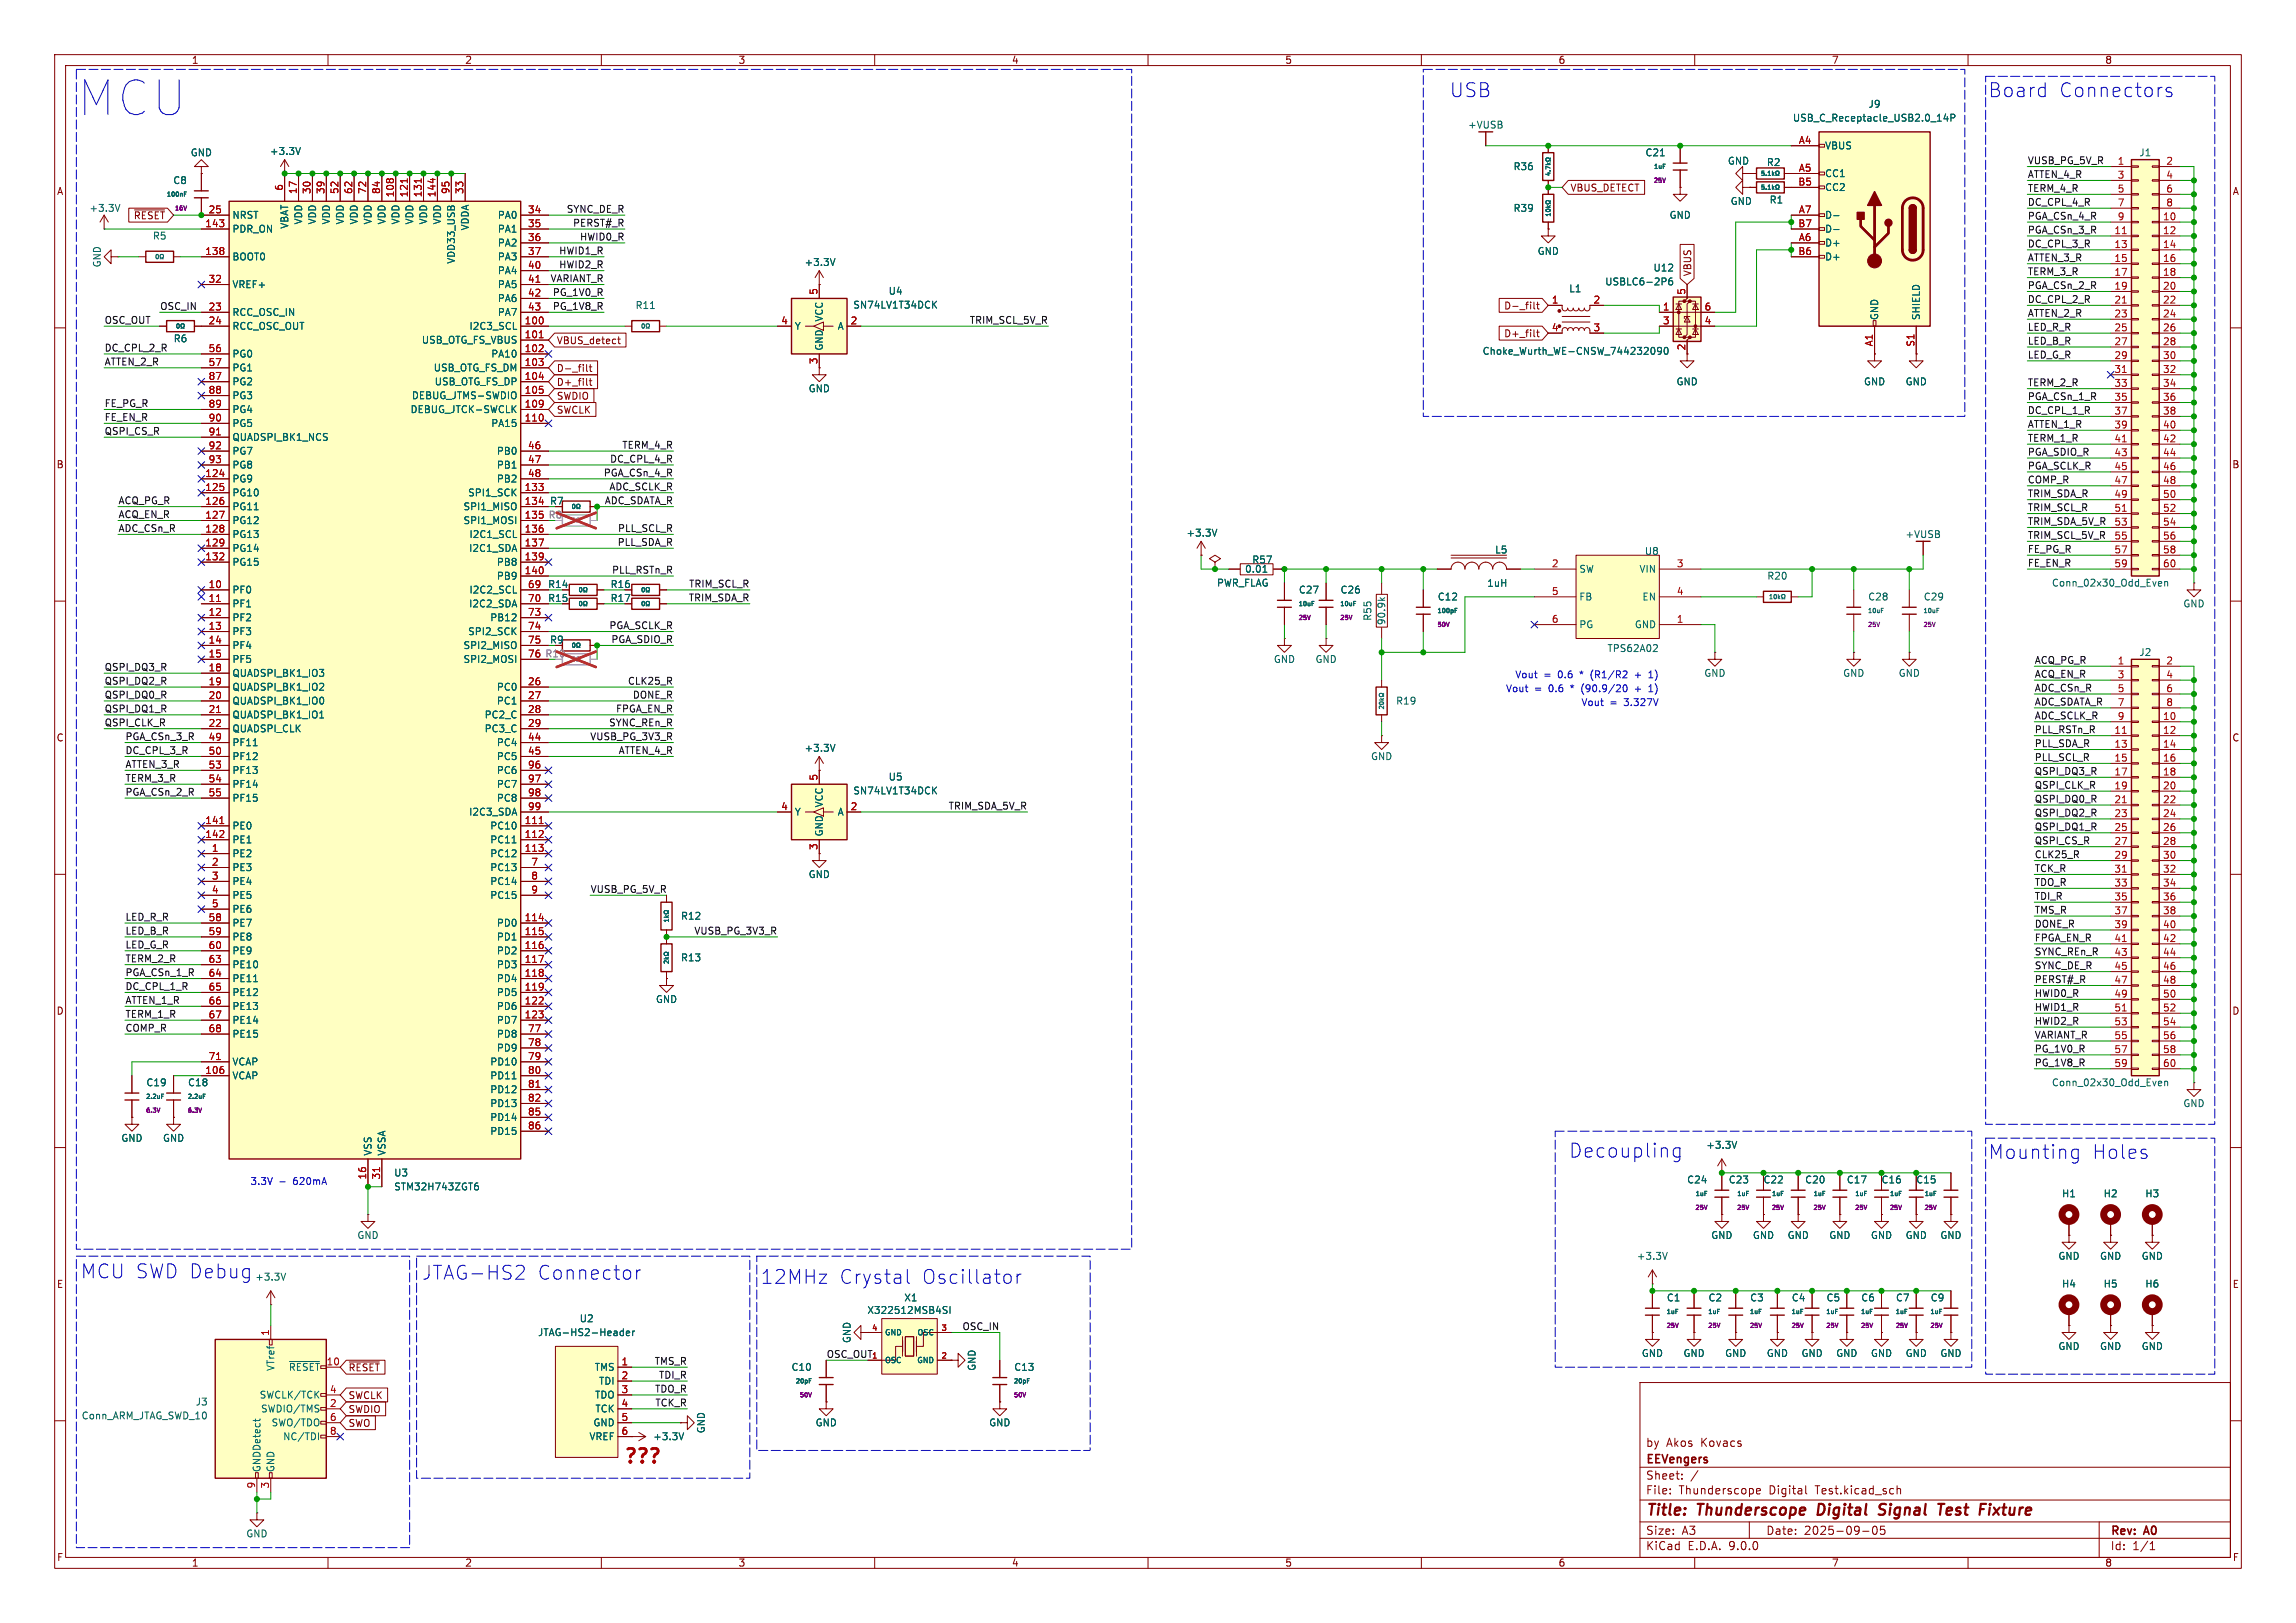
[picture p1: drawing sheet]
<svg xmlns="http://www.w3.org/2000/svg" width="420mm" height="297mm" viewBox="0 0 420 297" stroke-linecap="round" stroke-linejoin="round" font-family="sans-serif">
<defs><g id="words">
<text font-size="8.8" fill="#0000c2" x="14.4" y="21.4">MCU</text>
<g font-size="3.5" fill="#0000c2">
<text x="265.2" y="18">USB</text>
<text x="363.7" y="18">Board</text>
<text x="376.6" y="18">Connectors</text>
<text x="287" y="212.1">Decoupling</text>
<text x="363.7" y="212.3">Mounting</text>
<text x="382.7" y="212.3">Holes</text>
<text x="14.8" y="234.2">MCU SWD Debug</text>
<text x="77.2" y="234.4">JTAG-HS2</text>
<text x="98.3" y="234.4">Connector</text>
<text x="139.1" y="235.2">12MHz</text>
<text x="153.5" y="235.2">Crystal</text>
<text x="168.6" y="235.2">Oscillator</text>
</g>
<text font-size="3.5" fill="#c20000" x="113.8" y="268.5">???</text>
<g font-size="2.8" fill="#840000">
<text x="301" y="277.9">Title:</text>
<text x="310.6" y="277.9">Thunderscope</text>
<text x="333.4" y="277.9">Digital</text>
<text x="345.4" y="277.9">Signal</text>
<text x="357" y="277.9">Test</text>
<text x="365.4" y="277.9">Fixture</text>
</g>
<g font-size="2.1" fill="#840000">
<text x="301" y="268.2">EEVengers</text>
<text x="301" y="265">by</text>
<text x="304.8" y="265">Akos</text>
<text x="311.2" y="265">Kovacs</text>
<text x="301" y="273.7">File:</text>
<text x="301" y="271">Sheet:</text>
<text x="307.1" y="273.7">Thunderscope</text>
<text x="323.7" y="273.7">Digital</text>
<text x="332.2" y="273.7">Test.kicad_sch</text>
<text x="301" y="281.1">Size:</text>
<text x="307.6" y="281.1">A3</text>
<text x="323" y="281.1">Date:</text>
<text x="330" y="281.1">2025-09-05</text>
<text x="386" y="281.3">Rev:</text>
<text x="392.4" y="281.3">A0</text>
<text x="301" y="283.9">KiCad</text>
<text x="308.7" y="283.9">E.D.A.</text>
<text x="316.3" y="283.9">9.0.0</text>
<text x="386" y="283.9">Id:</text>
<text x="390.1" y="283.9">1/1</text>
</g>
<g font-size="1.8" fill="#840000">
<text x="35" y="11.9">1</text>
<text x="85" y="11.9">2</text>
<text x="135" y="11.9">3</text>
<text x="185" y="11.9">4</text>
<text x="235" y="11.9">5</text>
<text x="285" y="11.9">6</text>
<text x="335" y="11.9">7</text>
<text x="385" y="11.9">8</text>
<text x="10.3" y="35.9">A</text>
<text x="287.2" y="35.2">VBUS_DETECT</text>
<text x="408.3" y="35.9">A</text>
<text x="24.4" y="40.3">~{RESET}</text>
<text x="309.6" y="50.6" transform="rotate(-90 309.6 50.6)">VBUS</text>
<text x="275" y="56.8">D-_filt</text>
<text x="101.8" y="63.2">VBUS_detect</text>
<text x="275" y="61.9">D+_filt</text>
<text x="308.4" y="64.2" transform="rotate(-90 308.4 64.2)">2</text>
<text x="101.8" y="70.8">D+_filt</text>
<text x="101.8" y="68.3">D-_filt</text>
<text x="101.8" y="73.3">SWDIO</text>
<text x="101.8" y="75.9">SWCLK</text>
<text x="10.3" y="85.9">B</text>
<text x="408.2" y="85.9">B</text>
<text x="100.5" y="92.6">R7</text>
<text x="100.5" y="118">R9</text>
<text x="10.3" y="135.9">C</text>
<text x="408.2" y="135.9">C</text>
<text x="10.3" y="185.9">D</text>
<text x="408.2" y="185.9">D</text>
<text x="10.3" y="235.9">E</text>
<text x="408.3" y="235.9">E</text>
<text x="63.7" y="251.1">~{RESET}</text>
<text x="63.7" y="256.2">SWCLK</text>
<text x="63.7" y="261.3">SWO</text>
<text x="63.7" y="258.8">SWDIO</text>
<text x="10.3" y="285.9">F</text>
<text x="35" y="286.9">1</text>
<text x="85" y="286.9">2</text>
<text x="135" y="286.9">3</text>
<text x="185" y="286.9">4</text>
<text x="235" y="286.9">5</text>
<text x="285" y="286.9">6</text>
<text x="335" y="286.9">7</text>
<text x="385" y="286.9">8</text>
<text x="408.3" y="285.9">F</text>
</g>
<g font-size="1.8" fill="#006464">
<text x="268.4" y="23.7">+VUSB</text>
<text x="327.9" y="22.5">USB_C_Receptacle_USB2.0_14P</text>
<text x="341.7" y="19.9">J9</text>
<text x="34.8" y="28.8">GND</text>
<text x="49.3" y="28.5">+3.3V</text>
<text x="300.9" y="28.8">C21</text>
<text x="333.8" y="27.5">VBUS</text>
<text x="391.2" y="28.8">J1</text>
<text x="31.6" y="33.9">C8</text>
<text x="276.8" y="31.3">R36</text>
<text x="316" y="30.3">GND</text>
<text x="323.1" y="30.6">R2</text>
<text x="333.8" y="32.6">CC1</text>
<text x="333.8" y="35.2">CC2</text>
<text x="16.3" y="39">+3.3V</text>
<text x="42.4" y="40.2">NRST</text>
<text x="52.9" y="42" transform="rotate(-90 52.9 42)">VBAT</text>
<text x="55.5" y="41.2" transform="rotate(-90 55.5 41.2)">VDD</text>
<text x="58" y="41.2" transform="rotate(-90 58 41.2)">VDD</text>
<text x="60.6" y="41.2" transform="rotate(-90 60.6 41.2)">VDD</text>
<text x="63.1" y="41.2" transform="rotate(-90 63.1 41.2)">VDD</text>
<text x="65.6" y="41.2" transform="rotate(-90 65.6 41.2)">VDD</text>
<text x="68.2" y="41.2" transform="rotate(-90 68.2 41.2)">VDD</text>
<text x="70.7" y="41.2" transform="rotate(-90 70.7 41.2)">VDD</text>
<text x="73.3" y="41.2" transform="rotate(-90 73.3 41.2)">VDD</text>
<text x="75.8" y="41.2" transform="rotate(-90 75.8 41.2)">VDD</text>
<text x="78.3" y="41.2" transform="rotate(-90 78.3 41.2)">VDD</text>
<text x="80.9" y="41.2" transform="rotate(-90 80.9 41.2)">VDD</text>
<text x="91" y="40.2">PA0</text>
<text x="276.8" y="39">R39</text>
<text x="305.3" y="40.2">GND</text>
<text x="316.5" y="37.7">GND</text>
<text x="323.6" y="37.4">R1</text>
<text x="333.8" y="40.2">D-</text>
<text x="27.9" y="44">R5</text>
<text x="42.4" y="42.8">PDR_ON</text>
<text x="42.4" y="47.9">BOOT0</text>
<text x="86" y="42.3" transform="rotate(-90 86 42.3)">VDDA</text>
<text x="91" y="42.8">PA1</text>
<text x="91" y="45.3">PA2</text>
<text x="91" y="47.9">PA3</text>
<text x="281.2" y="46.8">GND</text>
<text x="333.8" y="42.8">D-</text>
<text x="333.8" y="45.3">D+</text>
<text x="333.8" y="47.9">D+</text>
<text x="18.6" y="49" transform="rotate(-90 18.6 49)">GND</text>
<text x="42.4" y="52.9">VREF+</text>
<text x="83.4" y="48.4" transform="rotate(-90 83.4 48.4)">VDD33_USB</text>
<text x="91" y="50.4">PA4</text>
<text x="91" y="52.9">PA5</text>
<text x="147.1" y="48.9">+3.3V</text>
<text x="286.9" y="53.7">L1</text>
<text x="293.5" y="52.4">USBLC6-2P6</text>
<text x="302.4" y="49.9">U12</text>
<text x="42.4" y="58">RCC_OSC_IN</text>
<text x="91" y="55.5">PA6</text>
<text x="91" y="58">PA7</text>
<text x="116.2" y="56.7">R11</text>
<text x="150.7" y="58.9" transform="rotate(-90 150.7 58.9)">VCC</text>
<text x="156" y="56.7">SN74LV1T34DCK</text>
<text x="162.5" y="54.1">U4</text>
<text x="343.8" y="58.7" transform="rotate(-90 343.8 58.7)">GND</text>
<text x="351.4" y="58.7" transform="rotate(-90 351.4 58.7)">SHIELD</text>
<text x="31.7" y="62.8">R6</text>
<text x="42.4" y="60.6">RCC_OSC_OUT</text>
<text x="42.4" y="65.6">PG0</text>
<text x="77.1" y="63.1">USB_OTG_FS_VBUS</text>
<text x="85.8" y="60.6">I2C3_SCL</text>
<text x="89.8" y="65.6">PA10</text>
<text x="145.3" y="60.6">Y</text>
<text x="150.7" y="64.3" transform="rotate(-90 150.7 64.3)">GND</text>
<text x="153.1" y="60.6">A</text>
<text x="271.1" y="65.1">Choke_Wurth_WE-CNSW_744232090</text>
<text x="42.4" y="68.2">PG1</text>
<text x="42.4" y="70.7">PG2</text>
<text x="79.2" y="68.2">USB_OTG_FS_DM</text>
<text x="79.4" y="70.7">USB_OTG_FS_DP</text>
<text x="147.8" y="72">GND</text>
<text x="306.6" y="70.7">GND</text>
<text x="340.9" y="70.7">GND</text>
<text x="348.5" y="70.7">GND</text>
<text x="42.4" y="73.3">PG3</text>
<text x="42.4" y="75.8">PG4</text>
<text x="75" y="75.8">DEBUG_JTCK-SWCLK</text>
<text x="75.2" y="73.3">DEBUG_JTMS-SWDIO</text>
<text x="42.4" y="78.3">PG5</text>
<text x="42.4" y="80.9">QUADSPI_BK1_NCS</text>
<text x="42.4" y="83.4">PG7</text>
<text x="89.8" y="78.3">PA15</text>
<text x="90.8" y="83.4">PB0</text>
<text x="42.4" y="86">PG8</text>
<text x="42.4" y="88.5">PG9</text>
<text x="90.8" y="86">PB1</text>
<text x="90.8" y="88.5">PB2</text>
<text x="42.4" y="91">PG10</text>
<text x="42.4" y="93.6">PG11</text>
<text x="84.7" y="93.6">SPI1_MISO</text>
<text x="85.5" y="91">SPI1_SCK</text>
<text x="42.4" y="96.1">PG12</text>
<text x="42.4" y="98.7">PG13</text>
<text x="42.4" y="101.2">PG14</text>
<text x="84.7" y="96.1">SPI1_MOSI</text>
<text x="85.7" y="101.2">I2C1_SDA</text>
<text x="85.8" y="98.7">I2C1_SCL</text>
<text x="216.9" y="98.4">+3.3V</text>
<text x="273.4" y="101.5">L5</text>
<text x="300.8" y="101.7">U8</text>
<text x="348.5" y="98.7">+VUSB</text>
<text x="42.4" y="103.7">PG15</text>
<text x="90.8" y="103.7">PB8</text>
<text x="90.8" y="106.3">PB9</text>
<text x="100.2" y="107.8">R14</text>
<text x="111.6" y="107.8">R16</text>
<text x="222.5" y="107.5">PWR_FLAG</text>
<text x="227.7" y="105">0.01</text>
<text x="229" y="103.3">R57</text>
<text x="271.9" y="107.6">1uH</text>
<text x="288.8" y="105">SW</text>
<text x="299.8" y="105">VIN</text>
<text x="323.2" y="106.3">R20</text>
<text x="375.2" y="107.5">Conn_02x30_Odd_Even</text>
<text x="42.4" y="108.8">PF0</text>
<text x="42.4" y="111.4">PF1</text>
<text x="42.4" y="113.9">PF2</text>
<text x="85.7" y="111.4">I2C2_SDA</text>
<text x="85.8" y="108.8">I2C2_SCL</text>
<text x="89.6" y="113.9">PB12</text>
<text x="100.2" y="110.3">R15</text>
<text x="111.6" y="110.3">R17</text>
<text x="237.5" y="108.8">C27</text>
<text x="245.1" y="108.8">C26</text>
<text x="251.1" y="113.7" transform="rotate(-90 251.1 113.7)">R55</text>
<text x="262.9" y="110.1">C12</text>
<text x="288.8" y="110.1">FB</text>
<text x="300.3" y="110.1">EN</text>
<text x="341.6" y="110.1">C28</text>
<text x="351.8" y="110.1">C29</text>
<text x="399.3" y="111.4">GND</text>
<text x="42.4" y="116.4">PF3</text>
<text x="42.4" y="119">PF4</text>
<text x="84.7" y="119">SPI2_MISO</text>
<text x="85.5" y="116.4">SPI2_SCK</text>
<text x="253.6" y="114.5" transform="rotate(-90 253.6 114.5)">90.9k</text>
<text x="288.8" y="115.2">PG</text>
<text x="293.9" y="119.5">TPS62A02</text>
<text x="298.9" y="115.2">GND</text>
<text x="42.4" y="121.5">PF5</text>
<text x="42.4" y="124.1">QUADSPI_BK1_IO3</text>
<text x="84.7" y="121.5">SPI2_MOSI</text>
<text x="232.9" y="121.5">GND</text>
<text x="240.5" y="121.5">GND</text>
<text x="311.7" y="124.1">GND</text>
<text x="337.1" y="124.1">GND</text>
<text x="347.2" y="124.1">GND</text>
<text x="391.2" y="120.2">J2</text>
<text x="42.4" y="126.6">QUADSPI_BK1_IO2</text>
<text x="42.4" y="129.1">QUADSPI_BK1_IO0</text>
<text x="42.4" y="131.7">QUADSPI_BK1_IO1</text>
<text x="88.6" y="131.7">PC2_C</text>
<text x="90.8" y="126.6">PC0</text>
<text x="90.8" y="129.1">PC1</text>
<text x="255.3" y="129.1">R19</text>
<text x="42.4" y="134.2">QUADSPI_CLK</text>
<text x="42.4" y="136.8">PF11</text>
<text x="88.6" y="134.2">PC3_C</text>
<text x="90.8" y="136.8">PC4</text>
<text x="147.1" y="137.8">+3.3V</text>
<text x="42.4" y="139.3">PF12</text>
<text x="42.4" y="141.8">PF13</text>
<text x="90.8" y="139.3">PC5</text>
<text x="90.8" y="141.8">PC6</text>
<text x="162.5" y="143">U5</text>
<text x="250.7" y="139.3">GND</text>
<text x="42.4" y="144.4">PF14</text>
<text x="42.4" y="146.9">PF15</text>
<text x="85.7" y="149.5">I2C3_SDA</text>
<text x="90.8" y="144.4">PC7</text>
<text x="90.8" y="146.9">PC8</text>
<text x="145.3" y="149.5">Y</text>
<text x="150.7" y="147.8" transform="rotate(-90 150.7 147.8)">VCC</text>
<text x="153.1" y="149.5">A</text>
<text x="156" y="145.6">SN74LV1T34DCK</text>
<text x="42.4" y="152">PE0</text>
<text x="42.4" y="154.5">PE1</text>
<text x="89.6" y="152">PC10</text>
<text x="89.6" y="154.5">PC11</text>
<text x="150.7" y="153.2" transform="rotate(-90 150.7 153.2)">GND</text>
<text x="42.4" y="157.1">PE2</text>
<text x="42.4" y="159.6">PE3</text>
<text x="89.6" y="157.1">PC12</text>
<text x="89.6" y="159.6">PC13</text>
<text x="147.8" y="160.9">GND</text>
<text x="42.4" y="162.2">PE4</text>
<text x="42.4" y="164.7">PE5</text>
<text x="42.4" y="167.2">PE6</text>
<text x="89.6" y="162.2">PC14</text>
<text x="89.6" y="164.7">PC15</text>
<text x="42.4" y="169.8">PE7</text>
<text x="42.4" y="172.3">PE8</text>
<text x="90.8" y="169.8">PD0</text>
<text x="90.8" y="172.3">PD1</text>
<text x="124.5" y="168.5">R12</text>
<text x="42.4" y="174.9">PE9</text>
<text x="42.4" y="177.4">PE10</text>
<text x="42.4" y="179.9">PE11</text>
<text x="90.8" y="174.9">PD2</text>
<text x="90.8" y="177.4">PD3</text>
<text x="90.8" y="179.9">PD4</text>
<text x="124.5" y="176.1">R13</text>
<text x="42.4" y="182.5">PE12</text>
<text x="42.4" y="185">PE13</text>
<text x="90.8" y="182.5">PD5</text>
<text x="90.8" y="185">PD6</text>
<text x="119.9" y="183.7">GND</text>
<text x="42.4" y="187.6">PE14</text>
<text x="42.4" y="190.1">PE15</text>
<text x="90.8" y="187.6">PD7</text>
<text x="90.8" y="190.1">PD8</text>
<text x="42.4" y="195.2">VCAP</text>
<text x="42.4" y="197.7">VCAP</text>
<text x="89.6" y="195.2">PD10</text>
<text x="89.6" y="197.7">PD11</text>
<text x="90.8" y="192.6">PD9</text>
<text x="26.7" y="199">C19</text>
<text x="34.3" y="199">C18</text>
<text x="89.6" y="200.3">PD12</text>
<text x="89.6" y="202.8">PD13</text>
<text x="375.2" y="199">Conn_02x30_Odd_Even</text>
<text x="399.3" y="202.8">GND</text>
<text x="22.1" y="209.1">GND</text>
<text x="29.7" y="209.1">GND</text>
<text x="89.6" y="205.3">PD14</text>
<text x="89.6" y="207.9">PD15</text>
<text x="68.2" y="211.6" transform="rotate(-90 68.2 211.6)">VSS</text>
<text x="70.7" y="211.6" transform="rotate(-90 70.7 211.6)">VSSA</text>
<text x="72" y="215.5">U3</text>
<text x="312" y="210.4">+3.3V</text>
<text x="72" y="218">STM32H743ZGT6</text>
<text x="308.5" y="216.8">C24</text>
<text x="316.1" y="216.8">C23</text>
<text x="322.5" y="216.8">C22</text>
<text x="330.1" y="216.8">C20</text>
<text x="337.7" y="216.8">C17</text>
<text x="344.1" y="216.8">C16</text>
<text x="350.4" y="216.8">C15</text>
<text x="377.1" y="219.3">H1</text>
<text x="384.7" y="219.3">H2</text>
<text x="392.3" y="219.3">H3</text>
<text x="65.3" y="226.9">GND</text>
<text x="312.9" y="226.9">GND</text>
<text x="320.5" y="226.9">GND</text>
<text x="326.9" y="226.9">GND</text>
<text x="334.5" y="226.9">GND</text>
<text x="342.1" y="226.9">GND</text>
<text x="348.5" y="226.9">GND</text>
<text x="354.8" y="226.9">GND</text>
<text x="299.3" y="230.7">+3.3V</text>
<text x="376.4" y="230.7">GND</text>
<text x="384" y="230.7">GND</text>
<text x="391.7" y="230.7">GND</text>
<text x="46.6" y="234.5">+3.3V</text>
<text x="165.3" y="238.4">X1</text>
<text x="304.8" y="238.4">C1</text>
<text x="312.4" y="238.4">C2</text>
<text x="320" y="238.4">C3</text>
<text x="327.7" y="238.4">C4</text>
<text x="334" y="238.4">C5</text>
<text x="340.4" y="238.4">C6</text>
<text x="346.7" y="238.4">C7</text>
<text x="353.1" y="238.4">C9</text>
<text x="377.1" y="235.8">H4</text>
<text x="384.7" y="235.8">H5</text>
<text x="392.3" y="235.8">H6</text>
<text x="98.3" y="244.7">JTAG-HS2-Header</text>
<text x="105.9" y="242.2">U2</text>
<text x="155.8" y="245.9" transform="rotate(-90 155.8 245.9)">GND</text>
<text x="158.6" y="240.6">X322512MSB4SI</text>
<text x="50.4" y="251" transform="rotate(-90 50.4 251)">VTref</text>
<text x="52.7" y="251.1">~{RESET}</text>
<text x="108.7" y="251.1">TMS</text>
<text x="144.7" y="251.1">C10</text>
<text x="178.7" y="251" transform="rotate(-90 178.7 251)">GND</text>
<text x="185.4" y="251.1">C13</text>
<text x="300.2" y="248.5">GND</text>
<text x="307.8" y="248.5">GND</text>
<text x="315.5" y="248.5">GND</text>
<text x="323.1" y="248.5">GND</text>
<text x="329.4" y="248.5">GND</text>
<text x="335.8" y="248.5">GND</text>
<text x="342.1" y="248.5">GND</text>
<text x="348.5" y="248.5">GND</text>
<text x="354.8" y="248.5">GND</text>
<text x="376.4" y="247.2">GND</text>
<text x="384" y="247.2">GND</text>
<text x="391.7" y="247.2">GND</text>
<text x="35.7" y="257.4">J3</text>
<text x="47.4" y="256.1">SWCLK/TCK</text>
<text x="108.8" y="256.1">TDO</text>
<text x="109.5" y="253.6">TDI</text>
<text x="14.8" y="259.9">Conn_ARM_JTAG_SWD_10</text>
<text x="47.6" y="258.7">SWDIO/TMS</text>
<text x="49.6" y="261.2">SWO/TDO</text>
<text x="51.7" y="263.8">NC/TDI</text>
<text x="107.7" y="263.8">VREF</text>
<text x="108.4" y="261.2">GND</text>
<text x="108.8" y="258.7">TCK</text>
<text x="119.4" y="263.8">+3.3V</text>
<text x="129.1" y="262.4" transform="rotate(-90 129.1 262.4)">GND</text>
<text x="149.1" y="261.2">GND</text>
<text x="180.8" y="261.2">GND</text>
<text x="47.9" y="269.5" transform="rotate(-90 47.9 269.5)">GNDDetect</text>
<text x="50.4" y="269.5" transform="rotate(-90 50.4 269.5)">GND</text>
<text x="45" y="281.5">GND</text>
</g>
<g font-size="1.8" fill="#a90000">
<text x="328.9" y="26.4">A4</text>
<text x="51.8" y="35" transform="rotate(-90 51.8 35)">6</text>
<text x="54.4" y="35.6" transform="rotate(-90 54.4 35.6)">17</text>
<text x="56.9" y="35.6" transform="rotate(-90 56.9 35.6)">30</text>
<text x="59.4" y="35.6" transform="rotate(-90 59.4 35.6)">39</text>
<text x="62" y="35.6" transform="rotate(-90 62 35.6)">52</text>
<text x="64.5" y="35.6" transform="rotate(-90 64.5 35.6)">62</text>
<text x="67.1" y="35.6" transform="rotate(-90 67.1 35.6)">72</text>
<text x="69.6" y="35.6" transform="rotate(-90 69.6 35.6)">84</text>
<text x="82.3" y="35.6" transform="rotate(-90 82.3 35.6)">95</text>
<text x="84.8" y="35.6" transform="rotate(-90 84.8 35.6)">33</text>
<text x="328.9" y="34">B5</text>
<text x="328.9" y="31.5">A5</text>
<text x="387.3" y="30.2">1</text>
<text x="387.3" y="32.8">3</text>
<text x="387.3" y="35.3">5</text>
<text x="396.2" y="30.2">2</text>
<text x="396.2" y="32.8">4</text>
<text x="396.2" y="35.3">6</text>
<text x="37.5" y="41.7">143</text>
<text x="38.1" y="39.1">25</text>
<text x="72.1" y="36.2" transform="rotate(-90 72.1 36.2)">108</text>
<text x="74.7" y="36.2" transform="rotate(-90 74.7 36.2)">121</text>
<text x="77.2" y="36.2" transform="rotate(-90 77.2 36.2)">131</text>
<text x="79.8" y="36.2" transform="rotate(-90 79.8 36.2)">144</text>
<text x="96.5" y="39.1">34</text>
<text x="96.5" y="41.7">35</text>
<text x="328.9" y="41.7">B7</text>
<text x="328.9" y="39.1">A7</text>
<text x="387.3" y="37.8">7</text>
<text x="387.3" y="40.4">9</text>
<text x="395.6" y="40.4">10</text>
<text x="396.2" y="37.8">8</text>
<text x="37.5" y="46.7">138</text>
<text x="96.5" y="44.2">36</text>
<text x="96.5" y="46.7">37</text>
<text x="328.9" y="46.7">B6</text>
<text x="328.9" y="44.2">A6</text>
<text x="386.7" y="42.9">11</text>
<text x="386.7" y="45.5">13</text>
<text x="395.6" y="42.9">12</text>
<text x="395.6" y="45.5">14</text>
<text x="38.1" y="51.8">32</text>
<text x="96.5" y="49.3">40</text>
<text x="96.5" y="51.8">41</text>
<text x="386.7" y="48">15</text>
<text x="386.7" y="50.5">17</text>
<text x="386.7" y="53.1">19</text>
<text x="395.6" y="48">16</text>
<text x="395.6" y="50.5">18</text>
<text x="395.6" y="53.1">20</text>
<text x="38.1" y="56.9">23</text>
<text x="38.1" y="59.4">24</text>
<text x="95.9" y="59.4">100</text>
<text x="96.5" y="54.4">42</text>
<text x="96.5" y="56.9">43</text>
<text x="142.8" y="59.4">4</text>
<text x="149.6" y="54" transform="rotate(-90 149.6 54)">5</text>
<text x="155.5" y="59.4">2</text>
<text x="283.8" y="55.6">1</text>
<text x="291.4" y="55.6">2</text>
<text x="304.1" y="56.9">1</text>
<text x="304.1" y="59.4">3</text>
<text x="308.4" y="54" transform="rotate(-90 308.4 54)">5</text>
<text x="311.7" y="56.9">6</text>
<text x="311.7" y="59.4">4</text>
<text x="386.7" y="55.6">21</text>
<text x="386.7" y="58.2">23</text>
<text x="395.6" y="55.6">22</text>
<text x="395.6" y="58.2">24</text>
<text x="38.1" y="64.5">56</text>
<text x="95.9" y="62">101</text>
<text x="95.9" y="64.5">102</text>
<text x="283.8" y="60.7">4</text>
<text x="291.4" y="60.7">3</text>
<text x="342.6" y="63.5" transform="rotate(-90 342.6 63.5)">A1</text>
<text x="350.3" y="63.5" transform="rotate(-90 350.3 63.5)">S1</text>
<text x="386.7" y="60.7">25</text>
<text x="386.7" y="63.2">27</text>
<text x="386.7" y="65.8">29</text>
<text x="395.6" y="60.7">26</text>
<text x="395.6" y="63.2">28</text>
<text x="395.6" y="65.8">30</text>
<text x="38.1" y="67.1">57</text>
<text x="38.1" y="69.6">87</text>
<text x="95.9" y="67.1">103</text>
<text x="95.9" y="69.6">104</text>
<text x="149.6" y="66.7" transform="rotate(-90 149.6 66.7)">3</text>
<text x="386.7" y="68.3">31</text>
<text x="386.7" y="70.9">33</text>
<text x="395.6" y="68.3">32</text>
<text x="395.6" y="70.9">34</text>
<text x="38.1" y="72.1">88</text>
<text x="38.1" y="74.7">89</text>
<text x="38.1" y="77.2">90</text>
<text x="95.9" y="72.1">105</text>
<text x="95.9" y="74.7">109</text>
<text x="95.9" y="77.2">110</text>
<text x="386.7" y="73.4">35</text>
<text x="386.7" y="75.9">37</text>
<text x="395.6" y="73.4">36</text>
<text x="395.6" y="75.9">38</text>
<text x="38.1" y="79.8">91</text>
<text x="38.1" y="82.3">92</text>
<text x="96.5" y="82.3">46</text>
<text x="386.7" y="78.5">39</text>
<text x="386.7" y="81">41</text>
<text x="386.7" y="83.6">43</text>
<text x="395.6" y="78.5">40</text>
<text x="395.6" y="81">42</text>
<text x="395.6" y="83.6">44</text>
<text x="37.5" y="87.4">124</text>
<text x="37.5" y="89.9">125</text>
<text x="38.1" y="84.8">93</text>
<text x="95.9" y="89.9">133</text>
<text x="96.5" y="84.8">47</text>
<text x="96.5" y="87.4">48</text>
<text x="386.7" y="86.1">45</text>
<text x="386.7" y="88.6">47</text>
<text x="395.6" y="86.1">46</text>
<text x="395.6" y="88.6">48</text>
<text x="37.5" y="92.5">126</text>
<text x="37.5" y="95">127</text>
<text x="95.9" y="92.5">134</text>
<text x="95.9" y="95">135</text>
<text x="386.7" y="91.2">49</text>
<text x="386.7" y="93.7">51</text>
<text x="395.6" y="91.2">50</text>
<text x="395.6" y="93.7">52</text>
<text x="37.5" y="97.5">128</text>
<text x="37.5" y="100.1">129</text>
<text x="95.9" y="97.5">136</text>
<text x="95.9" y="100.1">137</text>
<text x="386.7" y="96.3">53</text>
<text x="386.7" y="98.8">55</text>
<text x="386.7" y="101.3">57</text>
<text x="395.6" y="96.3">54</text>
<text x="395.6" y="98.8">56</text>
<text x="395.6" y="101.3">58</text>
<text x="37.5" y="102.6">132</text>
<text x="38.1" y="107.7">10</text>
<text x="95.9" y="102.6">139</text>
<text x="95.9" y="105.2">140</text>
<text x="96.5" y="107.7">69</text>
<text x="283.8" y="103.9">2</text>
<text x="306.6" y="103.9">3</text>
<text x="386.7" y="103.9">59</text>
<text x="395.6" y="103.9">60</text>
<text x="38.1" y="110.2">11</text>
<text x="38.1" y="112.8">12</text>
<text x="96.5" y="110.2">70</text>
<text x="96.5" y="112.8">73</text>
<text x="283.8" y="109">5</text>
<text x="306.6" y="109">4</text>
<text x="38.1" y="115.3">13</text>
<text x="38.1" y="117.9">14</text>
<text x="96.5" y="115.3">74</text>
<text x="96.5" y="117.9">75</text>
<text x="283.8" y="114">6</text>
<text x="306.6" y="114">1</text>
<text x="38.1" y="120.4">15</text>
<text x="38.1" y="122.9">18</text>
<text x="38.1" y="125.5">19</text>
<text x="96.5" y="125.5">26</text>
<text x="387.3" y="121.7">1</text>
<text x="387.3" y="124.2">3</text>
<text x="396.2" y="121.7">2</text>
<text x="396.2" y="124.2">4</text>
<text x="38.1" y="128">20</text>
<text x="38.1" y="130.6">21</text>
<text x="96.5" y="128">27</text>
<text x="96.5" y="130.6">28</text>
<text x="387.3" y="126.7">5</text>
<text x="387.3" y="129.3">7</text>
<text x="387.3" y="131.8">9</text>
<text x="395.6" y="131.8">10</text>
<text x="396.2" y="126.7">6</text>
<text x="396.2" y="129.3">8</text>
<text x="38.1" y="133.1">22</text>
<text x="38.1" y="135.6">49</text>
<text x="96.5" y="133.1">29</text>
<text x="96.5" y="135.6">44</text>
<text x="386.7" y="134.4">11</text>
<text x="386.7" y="136.9">13</text>
<text x="395.6" y="134.4">12</text>
<text x="395.6" y="136.9">14</text>
<text x="38.1" y="138.2">50</text>
<text x="38.1" y="140.7">53</text>
<text x="38.1" y="143.3">54</text>
<text x="96.5" y="138.2">45</text>
<text x="96.5" y="140.7">96</text>
<text x="96.5" y="143.3">97</text>
<text x="149.6" y="142.9" transform="rotate(-90 149.6 142.9)">5</text>
<text x="386.7" y="139.4">15</text>
<text x="386.7" y="142">17</text>
<text x="395.6" y="139.4">16</text>
<text x="395.6" y="142">18</text>
<text x="38.1" y="145.8">55</text>
<text x="96.5" y="145.8">98</text>
<text x="96.5" y="148.3">99</text>
<text x="142.8" y="148.3">4</text>
<text x="155.5" y="148.3">2</text>
<text x="386.7" y="144.5">19</text>
<text x="386.7" y="147.1">21</text>
<text x="386.7" y="149.6">23</text>
<text x="395.6" y="144.5">20</text>
<text x="395.6" y="147.1">22</text>
<text x="395.6" y="149.6">24</text>
<text x="37.5" y="150.9">141</text>
<text x="37.5" y="153.4">142</text>
<text x="38.7" y="156">1</text>
<text x="95.9" y="150.9">111</text>
<text x="95.9" y="153.4">112</text>
<text x="95.9" y="156">113</text>
<text x="149.6" y="155.6" transform="rotate(-90 149.6 155.6)">3</text>
<text x="386.7" y="152.1">25</text>
<text x="386.7" y="154.7">27</text>
<text x="395.6" y="152.1">26</text>
<text x="395.6" y="154.7">28</text>
<text x="38.7" y="158.5">2</text>
<text x="38.7" y="161">3</text>
<text x="97.1" y="158.5">7</text>
<text x="97.1" y="161">8</text>
<text x="386.7" y="157.2">29</text>
<text x="386.7" y="159.8">31</text>
<text x="395.6" y="157.2">30</text>
<text x="395.6" y="159.8">32</text>
<text x="38.7" y="163.6">4</text>
<text x="38.7" y="166.1">5</text>
<text x="97.1" y="163.6">9</text>
<text x="386.7" y="162.3">33</text>
<text x="386.7" y="164.8">35</text>
<text x="386.7" y="167.4">37</text>
<text x="395.6" y="162.3">34</text>
<text x="395.6" y="164.8">36</text>
<text x="395.6" y="167.4">38</text>
<text x="38.1" y="168.7">58</text>
<text x="38.1" y="171.2">59</text>
<text x="38.1" y="173.7">60</text>
<text x="95.9" y="168.7">114</text>
<text x="95.9" y="171.2">115</text>
<text x="95.9" y="173.7">116</text>
<text x="386.7" y="169.9">39</text>
<text x="386.7" y="172.5">41</text>
<text x="395.6" y="169.9">40</text>
<text x="395.6" y="172.5">42</text>
<text x="38.1" y="176.3">63</text>
<text x="38.1" y="178.8">64</text>
<text x="95.9" y="176.3">117</text>
<text x="95.9" y="178.8">118</text>
<text x="386.7" y="175">43</text>
<text x="386.7" y="177.5">45</text>
<text x="395.6" y="175">44</text>
<text x="395.6" y="177.5">46</text>
<text x="38.1" y="181.4">65</text>
<text x="38.1" y="183.9">66</text>
<text x="95.9" y="181.4">119</text>
<text x="95.9" y="183.9">122</text>
<text x="386.7" y="180.1">47</text>
<text x="386.7" y="182.6">49</text>
<text x="386.7" y="185.2">51</text>
<text x="395.6" y="180.1">48</text>
<text x="395.6" y="182.6">50</text>
<text x="395.6" y="185.2">52</text>
<text x="38.1" y="186.4">67</text>
<text x="38.1" y="189">68</text>
<text x="95.9" y="186.4">123</text>
<text x="96.5" y="189">77</text>
<text x="96.5" y="191.5">78</text>
<text x="386.7" y="187.7">53</text>
<text x="386.7" y="190.2">55</text>
<text x="395.6" y="187.7">54</text>
<text x="395.6" y="190.2">56</text>
<text x="37.5" y="196.6">106</text>
<text x="38.1" y="194.1">71</text>
<text x="96.5" y="194.1">79</text>
<text x="96.5" y="196.6">80</text>
<text x="386.7" y="192.8">57</text>
<text x="386.7" y="195.3">59</text>
<text x="395.6" y="192.8">58</text>
<text x="395.6" y="195.3">60</text>
<text x="96.5" y="199.1">81</text>
<text x="96.5" y="201.7">82</text>
<text x="96.5" y="204.2">85</text>
<text x="96.5" y="206.8">86</text>
<text x="67.1" y="215.9" transform="rotate(-90 67.1 215.9)">16</text>
<text x="69.6" y="215.9" transform="rotate(-90 69.6 215.9)">31</text>
<text x="49.3" y="244.5" transform="rotate(-90 49.3 244.5)">1</text>
<text x="59.6" y="249.9">10</text>
<text x="113.6" y="249.9">1</text>
<text x="60.3" y="255">4</text>
<text x="60.3" y="257.6">2</text>
<text x="113.6" y="252.5">2</text>
<text x="113.6" y="255">3</text>
<text x="113.6" y="257.6">4</text>
<text x="60.3" y="260.1">6</text>
<text x="60.3" y="262.6">8</text>
<text x="113.6" y="260.1">5</text>
<text x="113.6" y="262.6">6</text>
<text x="46.7" y="272.5" transform="rotate(-90 46.7 272.5)">9</text>
<text x="49.3" y="272.5" transform="rotate(-90 49.3 272.5)">3</text>
</g>
<g font-size="1.8" fill="#0f0f0f">
<text x="370.8" y="35.2">TERM_4_R</text>
<text x="370.8" y="32.7">ATTEN_4_R</text>
<text x="370.8" y="30.1">VUSB_PG_5V_R</text>
<text x="103.6" y="39">SYNC_DE_R</text>
<text x="104.7" y="41.6">PERST#_R</text>
<text x="370.8" y="37.8">DC_CPL_4_R</text>
<text x="370.8" y="40.3">PGA_CSn_4_R</text>
<text x="102.2" y="46.6">HWID1_R</text>
<text x="106" y="44.1">HWID0_R</text>
<text x="370.8" y="45.4">DC_CPL_3_R</text>
<text x="370.8" y="42.8">PGA_CSn_3_R</text>
<text x="370.8" y="47.9">ATTEN_3_R</text>
<text x="100.6" y="51.7">VARIANT_R</text>
<text x="102.2" y="49.2">HWID2_R</text>
<text x="370.8" y="50.5">TERM_3_R</text>
<text x="370.8" y="53">PGA_CSn_2_R</text>
<text x="19" y="59.3">OSC_OUT</text>
<text x="29.2" y="56.8">OSC_IN</text>
<text x="101" y="54.3">PG_1V0_R</text>
<text x="101" y="56.8">PG_1V8_R</text>
<text x="177.3" y="59.3">TRIM_SCL_5V_R</text>
<text x="370.8" y="58.1">ATTEN_2_R</text>
<text x="370.8" y="55.5">DC_CPL_2_R</text>
<text x="19" y="64.4">DC_CPL_2_R</text>
<text x="370.8" y="60.6">LED_R_R</text>
<text x="370.8" y="63.2">LED_B_R</text>
<text x="370.8" y="65.7">LED_G_R</text>
<text x="19" y="67">ATTEN_2_R</text>
<text x="370.8" y="70.8">TERM_2_R</text>
<text x="19" y="77.1">FE_EN_R</text>
<text x="19" y="74.6">FE_PG_R</text>
<text x="370.8" y="75.9">DC_CPL_1_R</text>
<text x="370.8" y="73.3">PGA_CSn_1_R</text>
<text x="19" y="79.7">QSPI_CS_R</text>
<text x="113.7" y="82.2">TERM_4_R</text>
<text x="370.8" y="78.4">ATTEN_1_R</text>
<text x="370.8" y="83.5">PGA_SDIO_R</text>
<text x="370.8" y="80.9">TERM_1_R</text>
<text x="110.3" y="87.3">PGA_CSn_4_R</text>
<text x="111.4" y="89.8">ADC_SCLK_R</text>
<text x="111.5" y="84.7">DC_CPL_4_R</text>
<text x="370.8" y="86">PGA_SCLK_R</text>
<text x="370.8" y="88.6">COMP_R</text>
<text x="21.6" y="92.4">ACQ_PG_R</text>
<text x="21.6" y="94.9">ACQ_EN_R</text>
<text x="110.5" y="92.4">ADC_SDATA_R</text>
<text x="370.8" y="91.1">TRIM_SDA_R</text>
<text x="370.8" y="93.6">TRIM_SCL_R</text>
<text x="21.6" y="97.4">ADC_CSn_R</text>
<text x="112.9" y="100">PLL_SDA_R</text>
<text x="112.9" y="97.4">PLL_SCL_R</text>
<text x="370.8" y="96.2">TRIM_SDA_5V_R</text>
<text x="370.8" y="98.7">TRIM_SCL_5V_R</text>
<text x="370.8" y="101.3">FE_PG_R</text>
<text x="111.9" y="105.1">PLL_RSTn_R</text>
<text x="126" y="107.6">TRIM_SCL_R</text>
<text x="370.8" y="103.8">FE_EN_R</text>
<text x="125.9" y="110.1">TRIM_SDA_R</text>
<text x="111.4" y="115.2">PGA_SCLK_R</text>
<text x="111.7" y="117.8">PGA_SDIO_R</text>
<text x="19" y="125.4">QSPI_DQ2_R</text>
<text x="19" y="122.8">QSPI_DQ3_R</text>
<text x="114.8" y="125.4">CLK25_R</text>
<text x="372.1" y="124.1">ACQ_EN_R</text>
<text x="372.1" y="121.6">ACQ_PG_R</text>
<text x="19" y="130.5">QSPI_DQ1_R</text>
<text x="19" y="127.9">QSPI_DQ0_R</text>
<text x="112.6" y="130.5">FPGA_EN_R</text>
<text x="115.7" y="127.9">DONE_R</text>
<text x="372.1" y="126.7">ADC_CSn_R</text>
<text x="372.1" y="129.2">ADC_SDATA_R</text>
<text x="372.1" y="131.7">ADC_SCLK_R</text>
<text x="19" y="133">QSPI_CLK_R</text>
<text x="22.9" y="135.5">PGA_CSn_3_R</text>
<text x="107.9" y="135.5">VUSB_PG_3V3_R</text>
<text x="111.3" y="133">SYNC_REn_R</text>
<text x="372.1" y="134.3">PLL_RSTn_R</text>
<text x="372.1" y="136.8">PLL_SDA_R</text>
<text x="22.9" y="138.1">DC_CPL_3_R</text>
<text x="22.9" y="140.6">ATTEN_3_R</text>
<text x="22.9" y="143.2">TERM_3_R</text>
<text x="113.1" y="138.1">ATTEN_4_R</text>
<text x="372.1" y="139.4">PLL_SCL_R</text>
<text x="372.1" y="141.9">QSPI_DQ3_R</text>
<text x="22.9" y="145.7">PGA_CSn_2_R</text>
<text x="173.4" y="148.2">TRIM_SDA_5V_R</text>
<text x="372.1" y="144.4">QSPI_CLK_R</text>
<text x="372.1" y="147">QSPI_DQ0_R</text>
<text x="372.1" y="149.5">QSPI_DQ2_R</text>
<text x="372.1" y="152.1">QSPI_DQ1_R</text>
<text x="372.1" y="154.6">QSPI_CS_R</text>
<text x="372.1" y="157.1">CLK25_R</text>
<text x="372.1" y="159.7">TCK_R</text>
<text x="107.9" y="163.5">VUSB_PG_5V_R</text>
<text x="372.1" y="162.2">TDO_R</text>
<text x="372.1" y="164.8">TDI_R</text>
<text x="372.1" y="167.3">TMS_R</text>
<text x="22.9" y="171.1">LED_B_R</text>
<text x="22.9" y="168.6">LED_R_R</text>
<text x="22.9" y="173.6">LED_G_R</text>
<text x="126.9" y="171.1">VUSB_PG_3V3_R</text>
<text x="372.1" y="169.8">DONE_R</text>
<text x="372.1" y="172.4">FPGA_EN_R</text>
<text x="22.9" y="178.7">PGA_CSn_1_R</text>
<text x="22.9" y="176.2">TERM_2_R</text>
<text x="372.1" y="180">PERST#_R</text>
<text x="372.1" y="174.9">SYNC_REn_R</text>
<text x="372.1" y="177.5">SYNC_DE_R</text>
<text x="22.9" y="181.3">DC_CPL_1_R</text>
<text x="22.9" y="183.8">ATTEN_1_R</text>
<text x="372.1" y="185.1">HWID1_R</text>
<text x="372.1" y="182.5">HWID0_R</text>
<text x="22.9" y="188.9">COMP_R</text>
<text x="22.9" y="186.3">TERM_1_R</text>
<text x="372.1" y="187.6">HWID2_R</text>
<text x="372.1" y="190.2">VARIANT_R</text>
<text x="372.1" y="195.2">PG_1V8_R</text>
<text x="372.1" y="192.7">PG_1V0_R</text>
<text x="176" y="243.5">OSC_IN</text>
<text x="119.7" y="249.8">TMS_R</text>
<text x="151.1" y="248.6">OSC_OUT</text>
<text x="119.7" y="254.9">TDO_R</text>
<text x="119.8" y="257.5">TCK_R</text>
<text x="120.4" y="252.4">TDI_R</text>
</g>
<g font-size="1.8" fill="#a1a1a1">
<text x="100.3" y="95.1">R8</text>
<text x="96.5" y="120.4">76 R10</text>
</g>
<g font-size="1.8" fill="#0000c2">
<text x="277.1" y="124.2">Vout</text>
<text x="282.4" y="124.2">=</text>
<text x="285.1" y="124.2">0.6</text>
<text x="289.3" y="124.2">*</text>
<text x="291.4" y="124.2">(R1/R2</text>
<text x="299.7" y="124.2">+</text>
<text x="302.5" y="124.2">1)</text>
<text x="275.4" y="126.8">Vout</text>
<text x="280.7" y="126.8">=</text>
<text x="283.4" y="126.8">0.6</text>
<text x="287.6" y="126.8">*</text>
<text x="289.2" y="129.3">Vout</text>
<text x="289.7" y="126.8">(90.9/20</text>
<text x="294.5" y="129.3">=</text>
<text x="297.2" y="129.3">3.327V</text>
<text x="299.7" y="126.8">+</text>
<text x="302.5" y="126.8">1)</text>
<text x="45.7" y="216.9">3.3V</text>
<text x="53.7" y="216.9">620mA</text>
</g>
<g font-size="1.4" fill="#a90000">
<text x="159.4" y="243.6">4</text>
<text x="172.1" y="243.6">3</text>
<text x="159.4" y="248.7">1</text>
<text x="172.1" y="248.7">2</text>
</g>
<g font-size="1.4" fill="#006464">
<text x="161.8" y="244.6">GND</text>
<text x="167.7" y="244.6">OSC</text>
<text x="161.8" y="249.6">OSC</text>
<text x="167.6" y="249.6">GND</text>
</g>
<g font-size="1.1" fill="#840084">
<text x="302.4" y="33.6">25V</text>
<text x="31.9" y="38.7">16V</text>
<text x="237.4" y="113.7">25V</text>
<text x="245" y="113.7">25V</text>
<text x="262.8" y="114.9">50V</text>
<text x="341.6" y="114.9">25V</text>
<text x="351.7" y="114.9">25V</text>
<text x="26.6" y="203.8">6.3V</text>
<text x="34.2" y="203.8">6.3V</text>
<text x="310" y="221.6">25V</text>
<text x="317.6" y="221.6">25V</text>
<text x="324" y="221.6">25V</text>
<text x="331.6" y="221.6">25V</text>
<text x="339.2" y="221.6">25V</text>
<text x="345.6" y="221.6">25V</text>
<text x="351.9" y="221.6">25V</text>
<text x="304.7" y="243.2">25V</text>
<text x="312.3" y="243.2">25V</text>
<text x="320" y="243.2">25V</text>
<text x="327.6" y="243.2">25V</text>
<text x="333.9" y="243.2">25V</text>
<text x="340.3" y="243.2">25V</text>
<text x="346.6" y="243.2">25V</text>
<text x="353" y="243.2">25V</text>
<text x="146.2" y="255.9">50V</text>
<text x="185.3" y="255.9">50V</text>
</g>
<g font-size="1.1" fill="#006464">
<text x="302.4" y="31.1">1uF</text>
<text x="30.4" y="36.2">100nF</text>
<text x="237.4" y="111.1">10uF</text>
<text x="245" y="111.1">10uF</text>
<text x="262.8" y="112.4">100pF</text>
<text x="341.6" y="112.4">10uF</text>
<text x="351.7" y="112.4">10uF</text>
<text x="26.6" y="201.3">2.2uF</text>
<text x="34.2" y="201.3">2.2uF</text>
<text x="310" y="219.1">1uF</text>
<text x="317.6" y="219.1">1uF</text>
<text x="324" y="219.1">1uF</text>
<text x="331.6" y="219.1">1uF</text>
<text x="339.2" y="219.1">1uF</text>
<text x="345.6" y="219.1">1uF</text>
<text x="351.9" y="219.1">1uF</text>
<text x="304.7" y="240.7">1uF</text>
<text x="312.3" y="240.7">1uF</text>
<text x="320" y="240.7">1uF</text>
<text x="327.6" y="240.7">1uF</text>
<text x="333.9" y="240.7">1uF</text>
<text x="340.3" y="240.7">1uF</text>
<text x="346.6" y="240.7">1uF</text>
<text x="353" y="240.7">1uF</text>
<text x="145.4" y="253.4">20pF</text>
<text x="185.3" y="253.4">20pF</text>
</g>
</g></defs>
<g fill="none" stroke="#840000" stroke-width=".18">
<path d="M10 10h400v277h-400zM12 12h396v273h-396zM60 10v2M110 10v2M160 10v2M210 10v2M260 10v2M310 10v2M360 10v2M283.2 26.7v1.2M283.2 33v1.3M320 31.8h1.3"/>
<path d="M320 34.3h1.3M326.4 31.8h1.3M326.4 34.3h1.3M10 60h2M350.5 64.8v1.2h-1.3l1.3 1.3 1.3-1.3h-1.3M350.5 64.8h.1M408 60h2M10 110h2M408 110h2M10 160h2M408 160h2M10 210h2"/>
<path d="M322.6 214.6v3.2M322.6 219.1v3.1M328.9 214.6v3.2M328.9 219.1v3.1M336.5 214.6v3.2M336.5 219.1v3.1M344.2 214.6v3.2M344.2 219.1v3.1M350.5 214.6v3.2M350.5 219.1v3.1M356.9 214.6v3.2M356.9 219.1v3.1"/>
<path d="M408 210h2M317.5 236.2v3.2M322.6 222.2v1.3h-1.3l1.3 1.3 1.2-1.3h-1.2M322.6 222.2h.1M328.9 222.2v1.3h-1.2l1.2 1.3 1.3-1.3h-1.3M328.9 222.2h.1M336.5 222.2v1.3h-1.2l1.2 1.3 1.3-1.3h-1.3M336.5 222.2h.1M344.2 222.2v1.3h-1.3l1.3 1.3 1.2-1.3h-1.2M344.2 222.2h.1M350.5 222.2v1.3h-1.3l1.3 1.3 1.3-1.3h-1.3M350.5 222.2h.1"/>
<path d="M350.5 236.2v3.2M356.9 222.2v1.3h-1.3l1.3 1.3 1.2-1.3h-1.2M356.9 222.2h.1M356.9 236.2v3.2M300 253h108v32h-108zM317.5 240.7v3.1M350.5 243.8v1.3h1.3l-1.3 1.3-1.3-1.3h1.3M350.5 243.8h.1M350.5 240.7v3.1M356.9 243.8v1.3h1.2l-1.2 1.3-1.3-1.3h1.3M356.9 243.8h.1M356.9 240.7v3.1"/>
<path d="M10 260h2M300 278.5h108M300 274.5h108M300 268.5h108M305.5 273.2v.2M305.5 272.5v.1M307.7 270.5v.2M307.7 269.8v.1M310.6 269.1l-1.3 1.9M320 278.5v3M321.3 272.9l.7-.2-.1-.2-.4-.1-.2 .2 .1 .7h.5M330.3 271.9v1.3l.2 .2"/>
<path d="M343 279.3a.85 .85 0 0 1-.1 1.5l-.2-.2-.2-.4 .2-.8M344.7 279.3h-.7l-.1 .7 .3-.1h.5l.1 .2-.1 .5-.2 .2-.6-.2M347 272.5l.2-.1 .4 .1 .1 .9M347 271.9v1.5M384 278.5v6.5M408 260h2M60 285v2M110 285v2M160 285v2M210 285v2M260 285v2M300 281.5h108"/>
<path d="M310 285v2M340.7 280.2h1.2M360 285v2M393.3 283.6h.9M393.3 282.5l.4-.4v1.5"/>
</g>
<path d="M332.7 275.2l-.2 2h.5M344.7 277a.85 .85 0 0 1-1.1 .1M344.7 275.2l-.7 .1a.46 .46 0 0 0-.2 .5 .46 .46 0 0 0 .3 .4l.6 .1M354.5 275.2h1.2M355.1 275.2l-.2 2M356.8 275.9l-.5 .1-.3 .9 .3 .3h.4M357.1 276.3l-1 .2M364.1 275.2l-.1 .1v.1M364.1 275.2v.1l-.1 .1M364.1 275.2l-.1 .2M365.8 275.9l-1.2 1.3" fill="none" stroke="#840000" stroke-width=".4"/>
<g fill="none" stroke="#840000" stroke-width=".25">
<path d="M271.8 24.1v2.6M282.2 27.9h2v5.1h-2zM321.3 30.7h5.1v2.1h-5.1zM321.3 33.3h5.1v2h-5.1zM321.3 217.8h2.5M321.3 219.1h2.5M327.7 217.8h2.5M327.7 219.1h2.5M335.3 217.8h2.5M335.3 219.1h2.5M342.9 217.8h2.5M342.9 219.1h2.5"/>
<path d="M349.2 217.8h2.6M349.2 219.1h2.6M355.6 217.8h2.5M355.6 219.1h2.5M316.2 239.4h2.6M349.2 239.4h2.6M355.6 239.4h2.5M316.2 240.7h2.6M349.2 240.7h2.6M355.6 240.7h2.5"/>
</g>
<path d="M102.9 119.6h5v2.1h-5z" fill="none" stroke="#a1a1a1" stroke-width=".25"/>
<path d="M107.9 120.7h1.3" fill="none" stroke="#a1a1a1" stroke-width=".18"/>
<path d="M105.1 120.3l-.1-.1a.39 .39 0 0 0-.3 .4 .39 .39 0 0 0 .4 .4M105.1 120.3h.1M105.1 120.3v.6M105.1 120.9v.1M105.5 121h.2v-.1a.34 .34 0 0 1-.2-.5 .34 .34 0 0 1 .5-.1l.1 .3-.2 .4h.2" fill="none" stroke="#989898" stroke-width=".18"/>
<path d="M101.8 119.2l7.2 2.9M109 119.2l-7.2 2.9" fill="none" stroke="#e12e31" stroke-width=".46"/>
<g fill="none" stroke="#006464" stroke-width=".18">
<path d="M282.8 30.1h.8M283 31.7h.6M283 29.8l.3 .3M283.3 31.6v.5l-.6-.2M283.5 31.3h.1M283.6 28.9v.2h-.2a.34 .34 0 0 0-.4-.2 .34 .34 0 0 0-.2 .5l.4 .1 .4-.2v.2M283.6 30.8l-.8-.4v.6M283.6 29.8l-.3 .2M322.7 31.3h-.4v.4h.4v.3h-.4M322.7 33.9h-.4v.3h.4v.4h-.4M323.1 32.1h.1M323.1 32v.1"/>
<path d="M323.1 34.6v.1M323.4 32.1h.5M323.4 31.5l.2-.2v.8M323.4 34.1l.2-.2v.8M323.4 34.7h.5M324.2 31.3v.8M324.2 33.9v.8M324.3 31.8l.2 .3M324.3 34.3l.2 .4M324.5 31.6l-.3 .3M324.5 34.1l-.3 .3M324.8 32.1h.2v-.1a.34 .34 0 0 1-.2-.5 .34 .34 0 0 1 .5-.1l.1 .3-.2 .4h.2"/>
<path d="M324.8 34.7h.2v-.2a.34 .34 0 0 1-.2-.5 .34 .34 0 0 1 .5-.1l.1 .4-.2 .4h.2"/>
</g>
<path d="M288.3 101.6h15.2v15.2h-15.2z" fill="#ffffc2"/>
<path d="M288.3 101.6h15.2v15.2h-15.2z" fill="none" stroke="#800000" stroke-width=".18"/>
<g fill="none" stroke="#840000" stroke-width=".18">
<path d="M283.2 34.3v1.3M307.3 26.7v3.1M307.3 31.1v3.2M318.8 34.3v1.3l-1.3-1.3 1.3-1.3v1.3h1.2M318.8 31.8v1.2l-1.3-1.2 1.3-1.3v1.3h1.2M320 34.3h.1M320 31.8h.1M283.2 55.9h2.5l.1 .7 .5 .3 .3-.2 .2-.3 .1 .3 .3 .2 .4-.1 .2-.4 .1 .3 .3 .2 .4-.1 .2-.4 .3 .5 .5-.1 .2-.4 .2 .4 .4 .1 .4-.3v-.7h2.6M283.2 41.9v1.3h-1.3l1.3 1.3 1.3-1.3h-1.3M283.2 41.9h.1M283.2 40.6v1.3M285.7 57.9h5.1"/>
<path d="M285.7 58.9h5.1M283.2 61h2.5l.1-.8 .5-.3 .3 .2 .2 .4 .1-.4 .3-.1 .4 .1 .2 .4 .2-.5h.5l.3 .5 .2-.4 .4-.1 .3 .1 .1 .4 .2-.4 .4-.1 .4 .3v.7h2.6M280.7 104.1h7.6M280.7 109.2h7.6M280.7 114.3h7.6M303.5 104.1h7.6M303.5 109.2h7.6M303.5 114.3h7.6M321.3 109.2h1.3M327.7 109.2h1.2M339.1 119.4v1.3h-1.3l1.3 1.2 1.3-1.2h-1.3M339.1 119.4h.1"/>
<path d="M401.3 106.7v1.3h1.3l-1.3 1.2-1.3-1.2h1.3M401.3 106.7h.1M252.7 134.6v1.3h-1.2l1.2 1.3 1.3-1.3h-1.3M252.7 134.6h.1M344.2 236.2v3.2M344.2 240.7v3.1"/>
</g>
<g fill="none" stroke="#006464" stroke-width=".18">
<path d="M282.8 37.9h.8M282.8 38.4a.39 .39 0 0 1 .5-.2 .39 .39 0 0 1 .2 .4 .39 .39 0 0 1-.4 .2 .39 .39 0 0 1-.3-.4zM283 37.6l.3 .3M283.6 36.7v.2h-.2a.34 .34 0 0 0-.4-.2 .34 .34 0 0 0-.2 .5l.4 .1 .4-.2v.2M283.6 39v.5M283.6 39.3h-.8l.2 .2M283.6 37.6l-.3 .3M303.7 28.5h.7M302.1 63.7l.2-.1a.68 .68 0 0 1 .4 .6 .68 .68 0 0 1-.4 .6l-.2-.1M303.9 64.1l-.2 .3h-.3l-.2-.3v-.3l.2-.2h.3l.2 .2a.84 .84 0 0 1-.3 1h-.3M304.5 63.7l.2-.1a.68 .68 0 0 1 .4 .6 .68 .68 0 0 1-.4 .6l-.3-.4zM302.9 118l.3 .2-.1 .3-.7 .7h.8"/>
<path d="M323.7 109.6h.5M323.7 109l.3-.2v.8M324.6 108.9l.1-.1a.39 .39 0 0 1 .3 .4 .39 .39 0 0 1-.4 .3l-.1-.2zM325.3 108.8v.8M325.4 109.3l.2 .3M325.6 109l-.3 .4M325.9 109.6h.2v-.2a.34 .34 0 0 1-.2-.4 .34 .34 0 0 1 .5-.2l.1 .4-.2 .4h.2"/>
</g>
<path d="M282.2 35.6h2v5h-2zM306.1 29.8h2.5M306.1 31.1h2.5M351.8 99.1v2.5M322.6 108.2h5.1v2h-5.1zM342.9 239.4h2.5M342.9 240.7h2.5" fill="none" stroke="#840000" stroke-width=".25"/>
<g fill="#840000" stroke="#840000" stroke-width=".18">
<circle cx="285.2" cy="56.9" r=".25"/>
<circle cx="285.2" cy="59.7" r=".25"/>
</g>
<path d="M389.9 29.2h5.1v76.2h-5.1z" fill="#ffffc2"/>
<path d="M389.9 29.2h5.1v76.2h-5.1z" fill="none" stroke="#840000" stroke-width=".25"/>
<g fill="none" stroke="#840000" stroke-width=".18">
<path d="M386.1 30.5h3.8M386.1 33h3.8M386.1 35.6h3.8M386.1 38.1h3.8M389.9 30.4h1.3v.2h-1.3zM389.9 32.9h1.3v.2h-1.3zM389.9 35.4h1.3v.3h-1.3zM389.9 38h1.3v.2h-1.3zM393.7 30.4h1.3v.2h-1.3zM393.7 32.9h1.3v.2h-1.3zM393.7 35.4h1.3v.3h-1.3zM393.7 38h1.3v.2h-1.3z"/>
<path d="M395 30.5h3.8M395 33h3.8M395 35.6h3.8M395 38.1h3.8M386.1 40.6h3.8M386.1 43.2h3.8M386.1 45.7h3.8M386.1 48.3h3.8M386.1 50.8h3.8M386.1 53.3h3.8M386.1 55.9h3.8M386.1 58.4h3.8"/>
<path d="M389.9 40.5h1.3v.3h-1.3zM389.9 43.1h1.3v.2h-1.3zM389.9 45.6h1.3v.2h-1.3zM389.9 48.1h1.3v.3h-1.3zM389.9 50.7h1.3v.2h-1.3zM389.9 53.2h1.3v.3h-1.3zM389.9 55.8h1.3v.2h-1.3zM389.9 58.3h1.3v.2h-1.3zM393.7 40.5h1.3v.3h-1.3zM393.7 43.1h1.3v.2h-1.3zM393.7 45.6h1.3v.2h-1.3zM393.7 48.1h1.3v.3h-1.3z"/>
<path d="M393.7 50.7h1.3v.2h-1.3zM393.7 53.2h1.3v.3h-1.3zM393.7 55.8h1.3v.2h-1.3zM393.7 58.3h1.3v.2h-1.3zM395 40.6h3.8M395 43.2h3.8M395 45.7h3.8M395 48.3h3.8M395 50.8h3.8M395 53.3h3.8M395 55.9h3.8M395 58.4h3.8"/>
<path d="M386.1 61h3.8M386.1 63.5h3.8M386.1 66h3.8M386.1 68.6h3.8M386.1 71.1h3.8M386.1 73.7h3.8M386.1 76.2h3.8M386.1 78.7h3.8M389.9 60.8h1.3v.3h-1.3zM389.9 63.4h1.3v.2h-1.3zM389.9 65.9h1.3v.3h-1.3zM389.9 68.5h1.3v.2h-1.3z"/>
<path d="M389.9 71h1.3v.2h-1.3zM389.9 73.5h1.3v.3h-1.3zM389.9 76.1h1.3v.2h-1.3zM389.9 78.6h1.3v.3h-1.3zM393.7 60.8h1.3v.3h-1.3zM393.7 63.4h1.3v.2h-1.3zM393.7 65.9h1.3v.3h-1.3zM393.7 68.5h1.3v.2h-1.3zM393.7 71h1.3v.2h-1.3zM393.7 73.5h1.3v.3h-1.3zM393.7 76.1h1.3v.2h-1.3zM393.7 78.6h1.3v.3h-1.3z"/>
<path d="M395 61h3.8M395 63.5h3.8M395 66h3.8M395 68.6h3.8M395 71.1h3.8M395 73.7h3.8M395 76.2h3.8M395 78.7h3.8M386.1 81.3h3.8M386.1 83.8h3.8M386.1 86.4h3.8M386.1 88.9h3.8"/>
<path d="M386.1 91.4h3.8M386.1 94h3.8M386.1 96.5h3.8M386.1 99.1h3.8M389.9 81.2h1.3v.2h-1.3zM389.9 83.7h1.3v.2h-1.3zM389.9 86.2h1.3v.3h-1.3zM389.9 88.8h1.3v.2h-1.3zM389.9 91.3h1.3v.3h-1.3zM389.9 93.9h1.3v.2h-1.3zM389.9 96.4h1.3v.2h-1.3zM389.9 98.9h1.3v.3h-1.3z"/>
<path d="M393.7 81.2h1.3v.2h-1.3zM393.7 83.7h1.3v.2h-1.3zM393.7 86.2h1.3v.3h-1.3zM393.7 88.8h1.3v.2h-1.3zM393.7 91.3h1.3v.3h-1.3zM393.7 93.9h1.3v.2h-1.3zM393.7 96.4h1.3v.2h-1.3zM393.7 98.9h1.3v.3h-1.3zM395 81.3h3.8M395 83.8h3.8M395 86.4h3.8M395 88.9h3.8"/>
<path d="M395 91.4h3.8M395 94h3.8M395 96.5h3.8M395 99.1h3.8M386.1 101.6h3.8M386.1 104.1h3.8M389.9 101.5h1.3v.2h-1.3zM389.9 104h1.3v.3h-1.3zM393.7 101.5h1.3v.2h-1.3zM393.7 104h1.3v.3h-1.3zM395 101.6h3.8M395 104.1h3.8"/>
</g>
<path d="M388.2 42.8h.8M388.2 55.5h.8M388.2 68.2h.8M388.2 80.9h.8M388.2 93.6h.8" fill="none" stroke="#a90000" stroke-width=".18"/>
<path d="M395 106.4l.4 .1v.2l-.6 .1M395.4 107.2l-.4 .1M396 106.5l.1-.1 .4 .1v.8M396 106.4v.9" fill="none" stroke="#006464" stroke-width=".18"/>
<path d="M389.9 120.7h5.1v76.2h-5.1z" fill="#ffffc2"/>
<path d="M26.7 46h5v2h-5zM30.5 58.7h5.1v2h-5.1zM337.8 111.1h2.6M337.8 112.4h2.6M348 111.1h2.5M348 112.4h2.5M251.7 125.7h2v5.1h-2zM389.9 120.7h5.1v76.2h-5.1z" fill="none" stroke="#840000" stroke-width=".25"/>
<g fill="none" stroke="#840000" stroke-width=".18">
<path d="M19 39.4l-.7 1.2M19 39.4l.8 1.2M19 39.4v2.5M19 41.9h.1M20.3 47v-1.3l-1.3 1.3 1.3 1.3v-1.3h1.3M21.6 47h.1M25.4 47h1.3M29.2 59.7h1.3M31.7 47h1.3M35.6 59.7h1.2M313.7 119.4v1.3h-1.3l1.3 1.2 1.3-1.2h-1.3M313.7 119.4h.1"/>
<path d="M339.1 108v3.1M339.1 112.4v3.2M349.2 119.4v1.3h-1.2l1.2 1.2 1.3-1.2h-1.3M349.2 119.4h.1M349.2 108v3.1M349.2 112.4v3.2M252.7 124.5v1.2M252.7 130.8v1.3M386.1 121.9h3.8M386.1 124.5h3.8M386.1 127h3.8M386.1 129.5h3.8"/>
<path d="M386.1 132.1h3.8M386.1 134.6h3.8M386.1 137.2h3.8M386.1 139.7h3.8M389.9 121.8h1.3v.2h-1.3zM389.9 124.3h1.3v.3h-1.3zM389.9 126.9h1.3v.2h-1.3zM389.9 129.4h1.3v.3h-1.3zM389.9 132h1.3v.2h-1.3zM389.9 134.5h1.3v.2h-1.3zM389.9 137h1.3v.3h-1.3zM389.9 139.6h1.3v.2h-1.3z"/>
<path d="M393.7 121.8h1.3v.2h-1.3zM393.7 124.3h1.3v.3h-1.3zM393.7 126.9h1.3v.2h-1.3zM393.7 129.4h1.3v.3h-1.3zM393.7 132h1.3v.2h-1.3zM393.7 134.5h1.3v.2h-1.3zM393.7 137h1.3v.3h-1.3zM393.7 139.6h1.3v.2h-1.3zM395 121.9h3.8M395 124.5h3.8M395 127h3.8M395 129.5h3.8"/>
<path d="M395 132.1h3.8M395 134.6h3.8M395 137.2h3.8M395 139.7h3.8M386.1 142.2h3.8M386.1 144.8h3.8M386.1 147.3h3.8M386.1 149.9h3.8M386.1 152.4h3.8M386.1 154.9h3.8M386.1 157.5h3.8M389.9 142.1h1.3v.3h-1.3z"/>
<path d="M389.9 144.7h1.3v.2h-1.3zM389.9 147.2h1.3v.2h-1.3zM389.9 149.7h1.3v.3h-1.3zM389.9 152.3h1.3v.2h-1.3zM389.9 154.8h1.3v.3h-1.3zM389.9 157.4h1.3v.2h-1.3zM389.9 159.9h1.3v.2h-1.3zM393.7 142.1h1.3v.3h-1.3zM393.7 144.7h1.3v.2h-1.3zM393.7 147.2h1.3v.2h-1.3zM393.7 149.7h1.3v.3h-1.3zM393.7 152.3h1.3v.2h-1.3z"/>
<path d="M393.7 154.8h1.3v.3h-1.3zM393.7 157.4h1.3v.2h-1.3zM393.7 159.9h1.3v.2h-1.3zM395 142.2h3.8M395 144.8h3.8M395 147.3h3.8M395 149.9h3.8M395 152.4h3.8M395 154.9h3.8M395 157.5h3.8M386.1 160h3.8M386.1 162.6h3.8"/>
<path d="M386.1 165.1h3.8M386.1 167.6h3.8M386.1 170.2h3.8M386.1 172.7h3.8M386.1 175.3h3.8M386.1 177.8h3.8M389.9 162.4h1.3v.3h-1.3zM389.9 165h1.3v.2h-1.3zM389.9 167.5h1.3v.3h-1.3zM389.9 170.1h1.3v.2h-1.3zM389.9 172.6h1.3v.2h-1.3zM389.9 175.1h1.3v.3h-1.3z"/>
<path d="M389.9 177.7h1.3v.2h-1.3zM393.7 162.4h1.3v.3h-1.3zM393.7 165h1.3v.2h-1.3zM393.7 167.5h1.3v.3h-1.3zM393.7 170.1h1.3v.2h-1.3zM393.7 172.6h1.3v.2h-1.3zM393.7 175.1h1.3v.3h-1.3zM393.7 177.7h1.3v.2h-1.3zM395 160h3.8M395 162.6h3.8M395 165.1h3.8M395 167.6h3.8"/>
<path d="M395 170.2h3.8M395 172.7h3.8M395 175.3h3.8M395 177.8h3.8M386.1 180.3h3.8M386.1 182.9h3.8M386.1 185.4h3.8M386.1 188h3.8M386.1 190.5h3.8M386.1 193h3.8M386.1 195.6h3.8M389.9 180.2h1.3v.3h-1.3z"/>
<path d="M389.9 182.8h1.3v.2h-1.3zM389.9 185.3h1.3v.2h-1.3zM389.9 187.8h1.3v.3h-1.3zM389.9 190.4h1.3v.2h-1.3zM389.9 192.9h1.3v.3h-1.3zM389.9 195.5h1.3v.2h-1.3zM393.7 180.2h1.3v.3h-1.3zM393.7 182.8h1.3v.2h-1.3zM393.7 185.3h1.3v.2h-1.3zM393.7 187.8h1.3v.3h-1.3zM393.7 190.4h1.3v.2h-1.3zM393.7 192.9h1.3v.3h-1.3z"/>
<path d="M393.7 195.5h1.3v.2h-1.3zM395 180.3h3.8M395 182.9h3.8M395 185.4h3.8M395 188h3.8M395 190.5h3.8M395 193h3.8M395 195.6h3.8M401.3 198.1v1.3h1.3l-1.3 1.3-1.3-1.3h1.3M401.3 198.1h.1"/>
</g>
<path d="M388.2 134.2h.8M388.2 146.9h.8M388.2 159.6h.8M388.2 172.3h.8M388.2 185h.8" fill="none" stroke="#a90000" stroke-width=".18"/>
<g fill="none" stroke="#006464" stroke-width=".18">
<path d="M21.9 37.4l-.4 1.3M28.6 46.6h.1a.39 .39 0 0 1 .3 .4 .39 .39 0 0 1-.4 .3l-.1-.3zM29.3 47.4h.2v-.2a.34 .34 0 0 1-.2-.5 .34 .34 0 0 1 .5-.1l.1 .4-.2 .4h.2M32.7 59.3h-.1a.39 .39 0 0 0-.3 .4 .39 .39 0 0 0 .4 .3M32.7 59.3h.1M32.7 59.3v.7M32.7 60h.1M33.1 60.1h.2v-.2a.34 .34 0 0 1-.2-.5 .34 .34 0 0 1 .5-.1l.1 .4-.2 .4h.2M344.1 111.3h.4M354.3 111.3h.4M252.3 128.1h.8M252.3 128.6a.39 .39 0 0 1 .5-.2 .39 .39 0 0 1 .3 .4 .39 .39 0 0 1-.5 .2 .39 .39 0 0 1-.3-.4z"/>
<path d="M252.6 127.8l.3 .3M253.1 129.2v.5l-.6-.5-.2 .2 .1 .3M253.1 126.9v.2h-.2a.34 .34 0 0 0-.4-.2 .34 .34 0 0 0-.2 .5l.4 .1 .4-.2v.2M253.1 127.8l-.3 .2M395 197.9h.4v.3l-.6 .1M395.4 198.6l-.4 .1M396 198l.1-.1h.4v.8M396 197.9v.8"/>
</g>
<path d="M41.9 36.8h53.3v175.3h-53.3z" fill="#ffffc2"/>
<path d="M35.6 34.9h2.5M35.6 36.2h2.5M41.9 36.8h53.3v175.3h-53.3z" fill="none" stroke="#840000" stroke-width=".25"/>
<g fill="none" stroke="#840000" stroke-width=".18">
<path d="M36.8 30.5h1.3l-1.3-1.3-1.2 1.3h1.2v1.3M36.8 31.8h.1M36.8 36.2v3.2h5.1M36.8 31.8v3.1M52.1 31.8h.1M52.1 29.2v7.6M52.1 29.2l-.8 1.3M52.1 29.2l.7 1.3M54.6 31.8v5M57.1 31.8v5M59.7 31.8v5M62.2 31.8v5"/>
<path d="M64.8 31.8v5M67.3 31.8v5M69.8 31.8v5M72.4 31.8v5M74.9 31.8v5M77.5 31.8v5M80 31.8v5M82.5 31.8v5M85.1 31.8v5M95.2 39.4h5.1M36.8 41.9h5.1M36.8 47h5.1"/>
<path d="M36.8 52.1h5.1M36.8 57.2h5.1M36.8 59.7h5.1M95.2 41.9h5.1M95.2 47h5.1M95.2 52.1h5.1M95.2 57.2h5.1M95.2 59.7h5.1M95.2 44.5h5.1M95.2 49.5h5.1M95.2 54.6h5.1M36.8 64.8h5.1"/>
<path d="M36.8 67.3h5.1M36.8 69.9h5.1M36.8 72.4h5.1M36.8 74.9h5.1M36.8 77.5h5.1M95.2 64.8h5.1M95.2 67.3h5.1M95.2 69.9h5.1M95.2 72.4h5.1M95.2 74.9h5.1M95.2 77.5h5.1M95.2 62.2h5.1"/>
<path d="M149.9 67.3v1.3h-1.3l1.3 1.3 1.2-1.3h-1.2M149.9 67.3h.1M36.8 80h5.1M36.8 82.6h5.1M36.8 85.1h5.1M36.8 87.6h5.1M36.8 90.2h5.1M36.8 92.7h5.1M36.8 95.3h5.1M36.8 97.8h5.1M95.2 82.6h5.1M95.2 85.1h5.1"/>
<path d="M95.2 87.6h5.1M95.2 90.2h5.1M95.2 92.7h5.1M95.2 95.3h5.1M95.2 97.8h5.1M36.8 100.3h5.1M36.8 102.9h5.1M36.8 108h5.1M36.8 110.5h5.1M36.8 113h5.1M36.8 115.6h5.1M36.8 118.1h5.1"/>
<path d="M95.2 100.3h5.1M95.2 102.9h5.1M95.2 108h5.1M95.2 110.5h5.1M95.2 113h5.1M95.2 115.6h5.1M95.2 118.1h5.1M95.2 105.4h5.1M36.8 120.7h5.1M36.8 123.2h5.1M36.8 125.7h5.1M36.8 128.3h5.1"/>
<path d="M36.8 130.8h5.1M36.8 133.4h5.1M36.8 135.9h5.1M36.8 138.4h5.1M95.2 120.7h5.1M95.2 125.7h5.1M95.2 128.3h5.1M95.2 130.8h5.1M95.2 133.4h5.1M95.2 135.9h5.1M95.2 138.4h5.1M36.8 141h5.1"/>
<path d="M36.8 143.5h5.1M36.8 146.1h5.1M36.8 151.1h5.1M36.8 153.7h5.1M36.8 156.2h5.1M36.8 158.8h5.1M95.2 141h5.1M95.2 143.5h5.1M95.2 146.1h5.1M95.2 151.1h5.1M95.2 153.7h5.1M95.2 156.2h5.1"/>
<path d="M95.2 158.8h5.1M95.2 148.6h5.1M36.8 161.3h5.1M36.8 163.8h5.1M36.8 166.4h5.1M36.8 168.9h5.1M36.8 171.5h5.1M36.8 174h5.1M36.8 176.5h5.1M36.8 179.1h5.1M95.2 161.3h5.1M95.2 163.8h5.1"/>
<path d="M95.2 168.9h5.1M95.2 171.5h5.1M95.2 174h5.1M95.2 176.5h5.1M95.2 179.1h5.1M36.8 181.6h5.1M36.8 184.2h5.1M36.8 186.7h5.1M36.8 189.2h5.1M36.8 194.3h5.1M36.8 196.9h5.1M95.2 181.6h5.1"/>
<path d="M95.2 184.2h5.1M95.2 186.7h5.1M95.2 189.2h5.1M95.2 194.3h5.1M95.2 196.9h5.1M95.2 191.8h5.1M95.2 199.4h5.1M67.3 212.1v5.1M69.8 212.1v5.1M95.2 201.9h5.1M95.2 204.5h5.1M95.2 207h5.1"/>
</g>
<g fill="none" stroke="#a90000" stroke-width=".18">
<path d="M74.5 32.7v.7M77.1 32.7v.7M79.2 32.7v.7M98 51.7h.8M39.6 79.6h.7M98.6 64.4h.8M98.6 61.8h.8M98.6 69h.8M99.3 63.2v.4M40.2 93.6h.8l-.5 1.2M40.2 86.8h.8M98.6 98.6h.8l-.5 1.3"/>
<path d="M98.6 91.9h.8M39.6 110.1h.7M40.2 102.5h.7M40.9 101.3v.4M39.6 130.4h.7M40.2 153.3h.7M40.2 150.7h.7M40.9 152.1v.4M98.6 153.3h.8M98.6 150.7h.8M99.3 152.1v.4M98.6 174.8h.8l-.5 1.3"/>
<path d="M98.6 168.1h.8M39.6 193.9h.7M98 199h.8M98.6 183.7h.8M99.3 182.6v.4M69.4 213.7v.7"/>
</g>
<g fill="none" stroke="#006464" stroke-width=".18">
<path d="M33.7 35.5h.3M33.7 35.1h.4M55 27l-.5 1.3M93.9 74.8l.5 .7M93.9 60.3h.6M94.2 71.8a.9 .9 0 0 1 0 1.1M94.4 74.2l-.7 .8M46.5 93.3h.7M93.9 98.4h.6M93.9 108.5h.6M46.3 136.5h.8M58.4 122.5h.8l-.4 .5"/>
<path d="M58.5 131.4h.7M58.7 130.3l.1-.2v1.3M59 125l.2 .3-.1 .3-.7 .7h.8M59.1 123l.1 .2-.1 .5M59.1 127.7l.1 .4-.1 .6M93.7 154.2h.7M46.4 179.6h.7M93.7 197.4h.7M86.9 217h.4l.2 .2-.1 .5h-.5M87.4 216.5l-.4 .1"/>
</g>
<path d="M144.8 54.6h10.1v10.2h-10.1z" fill="#ffffc2"/>
<path d="M115.6 58.7h5v2h-5zM144.8 54.6h10.1v10.2h-10.1zM102.9 117.1h5v2h-5z" fill="none" stroke="#840000" stroke-width=".25"/>
<g fill="none" stroke="#840000" stroke-width=".18">
<path d="M114.3 59.7h1.3M120.6 59.7h1.3M142.2 59.7h2.6M147.3 59.7h1.5M148.8 59.7l1.8-.8v1.6zM149.9 52.1h.1M149.9 49.5v5.1M149.9 49.5l-.8 1.3M149.9 49.5l.7 1.3M150.6 59.7h1.8M154.9 59.7h2.6M149.9 64.8v2.5"/>
<path d="M107.9 118.1h1.3"/>
</g>
<path d="M117.5 59.3h.1a.39 .39 0 0 1 .3 .4 .39 .39 0 0 1-.4 .3l-.1-.3zM119 56.5h.7M152.7 47.3l-.4 1.3M170.8 55.7l.5 .7M171.3 55.1l-.7 .7M118.2 60.1h.2v-.2a.34 .34 0 0 1-.2-.5 .34 .34 0 0 1 .5-.1l.1 .4-.2 .4h.2M104.8 117.7h.1a.39 .39 0 0 1 .3 .4 .39 .39 0 0 1-.4 .3l-.1-.2zM105.5 118.5h.2v-.2a.34 .34 0 0 1-.2-.4 .34 .34 0 0 1 .5-.2l.1 .4-.2 .4h.2" fill="none" stroke="#006464" stroke-width=".18"/>
<path d="M101.6 246.4h11.4v20.3h-11.4z" fill="#ffffc2"/>
<g fill="none" stroke="#840000" stroke-width=".18">
<path d="M107.9 92.7h1.3M24.1 196.9v3.1M31.7 196.9v3.1M24.1 204.5v1.2h1.3l-1.3 1.3-1.2-1.3h1.2M24.1 204.5h.1M24.1 201.3v3.2M31.7 204.5v1.2h1.3l-1.3 1.3-1.2-1.3h1.2M31.7 204.5h.1M31.7 201.3v3.2M49.5 238.8h.1M49.5 236.2l-.7 1.3M49.5 236.2l.8 1.3"/>
<path d="M49.5 236.2v2.6M67.3 222.2v1.3h1.3l-1.3 1.3-1.3-1.3h1.3M67.3 222.2h.1M101.6 246.4h11.4v20.3h-11.4zM113 250.2h2.6M113 252.7h2.6M113 255.3h2.6M113 257.8h2.6M113 260.3h2.6M113 262.9h2.6"/>
</g>
<g fill="none" stroke="#006464" stroke-width=".18">
<path d="M105.1 92.3h-.1a.39 .39 0 0 0-.3 .4 .39 .39 0 0 0 .4 .3M105.1 92.3h.1M105.1 92.3v.7M105.1 93h.1M105.5 93.1h.2v-.2a.34 .34 0 0 1-.2-.4 .34 .34 0 0 1 .5-.2l.1 .4-.2 .4h.2M29.6 200.6h.2M29.6 200.2h.3M37.2 200.6h.2M37.2 200.2h.4M52.3 233l-.5 1.3M113.7 243.6h.3M114 243.1v1.3"/>
<path d="M114 244.4h-.3M114.6 244l.6-.1-.1-.3h-.3l-.2 .2v.6h.5M115.7 243.6v.8M116.1 243.6l-.4 .2"/>
</g>
<path d="M102.9 91.7h5v2h-5zM22.9 200h2.5M22.9 201.3h2.5M30.5 200h2.5M30.5 201.3h2.5" fill="none" stroke="#840000" stroke-width=".25"/>
<path d="M102.9 94.2h5v2.1h-5z" fill="none" stroke="#a1a1a1" stroke-width=".25"/>
<path d="M107.9 95.3h1.3" fill="none" stroke="#a1a1a1" stroke-width=".18"/>
<path d="M104.8 94.9l.1-.1a.39 .39 0 0 1 .3 .4 .39 .39 0 0 1-.4 .4l-.1-.3zM105.5 95.6h.2v-.1a.34 .34 0 0 1-.2-.5 .34 .34 0 0 1 .5-.1l.1 .3-.2 .4h.2" fill="none" stroke="#989898" stroke-width=".18"/>
<path d="M101.8 93.8l7.2 2.9M109 93.8l-7.2 2.9" fill="none" stroke="#e12e31" stroke-width=".46"/>
<path d="M29.3 202.8l-.3 .8M36.9 202.8l-.3 .8" fill="none" stroke="#840084" stroke-width=".18"/>
<path d="M39.4 245.1h20.3v25.4h-20.3z" fill="#ffffc2"/>
<path d="M39.4 245.1h20.3v25.4h-20.3z" fill="none" stroke="#840000" stroke-width=".25"/>
<g fill="none" stroke="#840000" stroke-width=".18">
<path d="M342.9 64.8v1.2h-1.3l1.3 1.3 1.3-1.3h-1.3M342.9 64.8h.1M49.3 245.1h.5v1h-.5zM49.5 242.6v2.5M58.7 255h1v.5h-1zM58.7 257.6h1v.5h-1zM59.7 250.2h2.5M59.7 255.3h2.5M59.7 257.8h2.5M378.5 242.6v1.2h1.2l-1.2 1.3-1.3-1.3h1.3M378.5 242.6h.1M378.5 240v2.6"/>
<path d="M386.1 242.6v1.2h1.2l-1.2 1.3-1.3-1.3h1.3M386.1 242.6h.1M386.1 240v2.6M393.7 242.6v1.2h1.3l-1.3 1.3-1.3-1.3h1.3M393.7 242.6h.1M393.7 240v2.6M46.7 269.5h.5v1h-.5zM47 270.5v2.5M49.3 269.5h.5v1h-.5zM49.5 270.5v2.5M58.7 260.1h1v.5h-1zM58.7 262.6h1v.5h-1z"/>
<path d="M59.7 260.3h2.5M59.7 262.9h2.5"/>
</g>
<path d="M46.7 259.7v.4M47.6 259.7l-.1 .2M53 249.1h5.4M58.3 262.2v1.3" fill="none" stroke="#006464" stroke-width=".18"/>
<g fill="none" stroke="#840000" stroke-width="1.3">
<circle cx="378.5" cy="238.8" r="1.27"/>
<circle cx="386.1" cy="238.8" r="1.27"/>
<circle cx="393.7" cy="238.8" r="1.27"/>
</g>
<path d="M332.7 24.1h20.4v35.6h-20.4z" fill="#ffffc2"/>
<g fill="none" stroke="#840000" stroke-width=".18">
<path d="M327.7 26.7h5M327.7 31.8h5M327.7 34.3h5M327.7 39.4h5M332.7 26.4h1.1v.5h-1.1zM332.7 31.5h1.1v.5h-1.1zM332.7 34h1.1v.5h-1.1zM332.7 39.1h1.1v.5h-1.1zM327.7 41.9h5M327.7 44.5h5M327.7 47h5M332.7 41.7h1.1v.5h-1.1z"/>
<path d="M332.7 44.2h1.1v.5h-1.1zM332.7 46.7h1.1v.5h-1.1zM342.6 58.7h.6v1h-.6zM342.9 59.7v5.1M350.5 59.7v5.1M149.9 156.2v1.3h-1.3l1.3 1.3 1.2-1.3h-1.2M149.9 156.2h.1M315 214.6v3.2M315 219.1v3.1M309.9 236.2v3.2M315 222.2v1.3h-1.3l1.3 1.3 1.2-1.3h-1.2M315 222.2h.1"/>
<path d="M378.5 226.1v1.2h1.2l-1.2 1.3-1.3-1.3h1.3M378.5 226.1h.1M378.5 223.5v2.6M386.1 226.1v1.2h1.2l-1.2 1.3-1.3-1.3h1.3M386.1 226.1h.1M386.1 223.5v2.6M393.7 226.1v1.2h1.3l-1.3 1.3-1.3-1.3h1.3M393.7 226.1h.1M393.7 223.5v2.6M309.9 243.8v1.3h1.2l-1.2 1.3-1.3-1.3h1.3M309.9 243.8h.1M309.9 240.7v3.1"/>
<path d="M317.5 243.8v1.3h1.3l-1.3 1.3-1.3-1.3h1.3M317.5 243.8h.1M47 276.9v1.2h1.3l-1.3 1.3-1.3-1.3h1.3M47 276.9h.1M115.6 262.9h.1M115.6 262.9h2.5M116.8 262.1l1.3 .8M118.1 262.9l-1.3 .8M124.5 260.3h1.2v-1.2l1.3 1.2-1.3 1.3v-1.3M124.5 260.3h.1"/>
</g>
<path d="M332.7 24.1h20.4v35.6h-20.4zM349.2 38.1a.64 .64 0 0 1 .7-.6 .64 .64 0 0 1 .6 .6M349.2 45.7a.64 .64 0 0 0 .7 .7 .64 .64 0 0 0 .6-.7M313.7 217.8h2.5M313.7 219.1h2.5M308.6 239.4h2.5M308.6 240.7h2.5" fill="none" stroke="#840000" stroke-width=".25"/>
<path d="M342.9 37.6v10.2M348.5 36.8a1.91 1.91 0 0 1 2.1-.5 1.91 1.91 0 0 1 1.2 1.8v7.6a1.91 1.91 0 0 1-1.9 1.9 1.91 1.91 0 0 1-1.9-1.9v-7.7l.2-.7zM340.4 40.1v1.3l2.5 2.5M345.4 41.4v1.3l-2.5 2.5" fill="none" stroke="#840000" stroke-width=".51"/>
<g fill="#840000" stroke="#840000" stroke-width=".25">
<path d="M349.2 38.1h1.3v7.6h-1.3z"/>
<path d="M349.4 37.7a.64 .64 0 0 1 .7-.2 .64 .64 0 0 1 .4 .6h-1.3z"/>
<path d="M349.2 45.7h1.3a.64 .64 0 0 1-.6 .7 .64 .64 0 0 1-.7-.7z"/>
<path d="M342.9 35.1l1.3 2.5h-2.6z"/>
<path d="M339.7 38.9h1.3v1.2h-1.3z"/>
<circle cx="345.4" cy="40.8" r=".63"/>
</g>
<circle cx="342.9" cy="47.8" r="1.27" fill="#840000" stroke="#840000" stroke-width=".18"/>
<path d="M335.4 39.5h1M355.9 20.8l-.3 .9h.8M356.2 21.3v.9M356.9 21.6l.6-.1 .1-.2-.1-.3-.6-.1v1.3M335.4 42h1M125.1 262.2l-.5 1.3" fill="none" stroke="#006464" stroke-width=".18"/>
<g fill="none" stroke="#840000" stroke-width="1.3">
<circle cx="378.5" cy="222.2" r="1.27"/>
<circle cx="386.1" cy="222.2" r="1.27"/>
<circle cx="393.7" cy="222.2" r="1.27"/>
</g>
<path d="M144.8 143.5h10.1v10.2h-10.1z" fill="#ffffc2"/>
<path d="M144.8 143.5h10.1v10.2h-10.1zM120.9 165.1h2v5.1h-2zM301 239.4h2.5M323.8 239.4h2.6M330.2 239.4h2.5M336.5 239.4h2.6M301 240.7h2.5M323.8 240.7h2.6M330.2 240.7h2.5M336.5 240.7h2.6" fill="none" stroke="#840000" stroke-width=".25"/>
<g fill="none" stroke="#840000" stroke-width=".18">
<path d="M307.3 34.3v1.3h-1.2l1.2 1.2 1.3-1.2h-1.3M307.3 34.3h.1M308.6 64.8v1.2h-1.3l1.3 1.3 1.3-1.3h-1.3M149.9 138.4v5.1M149.9 138.4l-.8 1.3M149.9 138.4l.7 1.3M142.2 148.6h2.6M147.3 148.6h1.5M148.8 148.6l1.8-.8v1.6zM149.9 141h.1M149.9 153.7v2.5M150.6 148.6h1.8"/>
<path d="M154.9 148.6h2.6M121.9 163.8v1.3M121.9 170.2v1.3M315 214.6h.1M315 212.1l.7 1.3M315 212.1l-.8 1.3M315 212.1v2.5M302.3 234.9h.1M302.3 232.4v2.5M302.3 236.2v3.2M302.3 232.4l-.8 1.3M302.3 232.4l.7 1.3"/>
<path d="M325.1 236.2v3.2M331.5 236.2v3.2M337.8 236.2v3.2M302.3 243.8v1.3h1.2l-1.2 1.3-1.3-1.3h1.3M302.3 243.8h.1M302.3 240.7v3.1M325.1 243.8v1.3h1.3l-1.3 1.3-1.3-1.3h1.3M325.1 243.8h.1M325.1 240.7v3.1M331.5 243.8v1.3h1.2l-1.2 1.3-1.3-1.3h1.3M331.5 243.8h.1M331.5 240.7v3.1"/>
<path d="M337.8 243.8v1.3h1.3l-1.3 1.3-1.3-1.3h1.3M337.8 243.8h.1M337.8 240.7v3.1M344.2 243.8v1.3h1.2l-1.2 1.3-1.3-1.3h1.3M344.2 243.8h.1"/>
</g>
<path d="M152.7 136.2l-.4 1.3M170.8 144.6l.5 .7M171.3 144l-.7 .7M121.5 167.8h.8M121.7 167.5l.4 .3M122.3 166.6v.2h-.2a.34 .34 0 0 0-.4-.2 .34 .34 0 0 0-.2 .5l.4 .1 .4-.2v.2M122.3 168.2v.4M122.3 168.4h-.8l.2 .2M122.3 167.5l-.3 .3M317.7 208.9l-.4 1.2M305 229.2l-.4 1.2" fill="none" stroke="#006464" stroke-width=".18"/>
<path d="M306.1 54.4h5v8.1h-5z" fill="#ffffc2"/>
<g fill="#840000" stroke="#840000" stroke-width=".18">
<circle cx="307.1" cy="57.1" r=".25"/>
<circle cx="308.1" cy="55.1" r=".25"/>
<circle cx="308.1" cy="61.7" r=".25"/>
<circle cx="309.1" cy="55.1" r=".25"/>
<circle cx="309.1" cy="61.7" r=".25"/>
<circle cx="310.1" cy="59.7" r=".25"/>
</g>
<g fill="none" stroke="#840000" stroke-width=".18">
<path d="M303.5 57.2h10.2M303.5 59.7h10.2M306.6 55.6h1M307.1 55.6l.5 1h-1zM308.1 55.1h-1v6.6h1M308.6 52.1v2.5l-.5 .5h1l-.5 .5v5.6l-.5 .5h1l-.5 .5v2.6M308.6 57.9l.5 1h-1zM309.1 57.9h-1v.4M309.1 55.1h1v6.6h-1M309.6 55.6h1M310.1 55.6l.5 1h-1zM306.6 60.2h1"/>
<path d="M307.1 60.2l.5 1h-1zM309.6 60.2h1M310.1 60.2l.5 1h-1zM219.7 99.1l-.8 1.2M219.7 99.1l.8 1.2M219.7 99.1v2.5M219.7 101.6h.1M222.2 102.9l-1-.7 1-.6 1.1 .6-1.1 .7v1.2M222.2 104.1h.1M224.8 104.1h2M226.9 103.2h6v2h-6zM233 104.1h1.9"/>
<path d="M234.9 116.8v1.3h-1.2l1.2 1.3 1.3-1.3h-1.3M234.9 116.8h.1M234.9 106.7v3.2M234.9 111.1v3.2M242.6 116.8v1.3h-1.3l1.3 1.3 1.2-1.3h-1.2M242.6 116.8h.1M242.6 106.7v3.2M242.6 111.1v3.2M251.8 108.8h2v6h-2zM252.7 106.7v2M252.7 114.8v2M121.9 179.1v1.2h1.3l-1.3 1.3-1.3-1.3h1.3"/>
<path d="M121.9 179.1h.1M121.9 171.5v1.2M121.9 177.8v1.3"/>
</g>
<path d="M306.1 54.4h5v8.1h-5zM233.7 109.9h2.5M233.7 111.1h2.5M241.3 109.9h2.5M241.3 111.1h2.5M120.9 172.7h2v5.1h-2z" fill="none" stroke="#840000" stroke-width=".25"/>
<g fill="none" stroke="#006464" stroke-width=".18">
<path d="M304.6 50.9l.2 .2-.2 .4M305.8 50.9h-.3a.86 .86 0 0 0 0 1.2l.4-.1 .1-.4-.3-.2h-.3l-.2 .2M222.6 96.8l-.4 1.3M231 104.7h.7M231.4 103.4v1.3M240 110.1h.4M247.6 110.1h.4M252.5 109.4l.4 .5M253.3 109.4l-.5 .3M121.5 175.5h.8M121.7 175.2l.4 .3M122.3 175.8v.5l-.6-.5-.2 .2 .1 .3"/>
<path d="M122.3 174.3v.1h-.2a.34 .34 0 0 0-.4-.1 .34 .34 0 0 0-.2 .4l.4 .2 .4-.2v.2M122.3 175.2l-.3 .2"/>
</g>
<path d="M161.3 241.3h10.1v10.2h-10.1z" fill="#ffffc2"/>
<g fill="none" stroke="#840000" stroke-width=".18">
<path d="M23.6 38.1h7l1.1 1.3-1.1 1.2h-7zM24.6 38.4h5.5M36.8 31.8h.1M36.8 36.2v3.2h5.1M36.8 31.8v3.1M52.1 31.8h.1M52.1 31.8v5M54.6 31.8v5M57.1 31.8v5M59.7 31.8v5M62.2 31.8v5M64.8 31.8v5"/>
<path d="M67.3 31.8v5M69.8 31.8v5M72.4 31.8v5M74.9 31.8v5M77.5 31.8v5M80 31.8v5M82.5 31.8v5M85.1 31.8v5M95.2 39.4h5.1M283.2 26.7v1.2M283.2 33v2.6M286.9 33h13.9v2.6h-13.9l-1.2-1.3z"/>
<path d="M307.3 34.3h.1M307.3 26.7v3.1M307.3 31.1v3.2M320 34.3h.1M320 31.8h.1M320 31.8h1.3M320 34.3h1.3M326.4 31.8h6.3M326.4 34.3h6.3M327.7 26.7h5M327.7 39.4h5M29.2 59.7h1.3"/>
<path d="M35.6 59.7h6.3M36.8 57.2h5.1M36.8 41.9h5.1M36.8 47h5.1M36.8 52.1h5.1M95.2 57.2h5.1M95.2 59.7h5.1M95.2 41.9h5.1M95.2 44.5h5.1M95.2 47h5.1M95.2 52.1h5.1M95.2 49.5h5.1"/>
<path d="M95.2 54.6h5.1M142.2 59.7h2.6M149.9 52.1h.1M149.9 52.1v2.5M154.9 59.7h2.6M274.2 54.6h7.9l1.1 1.3-1.1 1.3h-7.9zM274.2 59.7h7.9l1.1 1.3-1.1 1.2h-7.9zM280.6 55.3v1.1l.2 .2M281.1 55.7h.5M281.3 55.3v1.1l.3 .2M283.2 41.9h.1M283.2 40.6v1.3"/>
<path d="M283.2 55.9h2.5M290.8 55.9h2.6M303.5 57.2h2.6M303.5 59.7h2.6M307.3 44.7h2.6v6.3l-1.3 1.1-1.3-1.1zM308.6 52.1v2.5M311.1 57.2h2.6M311.1 59.7h2.6M327.7 41.9h5M327.7 44.5h5M327.7 47h5M342.9 59.7v5.1"/>
<path d="M350.5 59.7v5.1M36.8 64.8h5.1M36.8 67.3h5.1M36.8 69.9h5.1M36.8 72.4h5.1M36.8 74.9h5.1M36.8 77.5h5.1M95.2 64.8h5.1M95.2 67.3h5.1M95.2 69.9h5.1M95.2 72.4h5.1M95.2 74.9h5.1"/>
<path d="M95.2 77.5h5.1M95.2 62.2h5.1M101.4 71.1h7.2v2.6h-7.2l-1.1-1.3zM101.4 68.6h7.9v2.5h-7.9l-1.1-1.2zM101.4 66h7.9v2.6h-7.9l-1.1-1.3zM101.4 73.7h7.6v2.5h-7.6l-1.1-1.3zM101.4 61h13.1v2.5h-13.1l-1.1-1.3zM107.3 66.7v1.1l.2 .2M107.4 70.5h.1M107.8 69.7h.5M107.8 67.1h.5M108 66.7v1.1l.3 .2"/>
<path d="M108 69.3v1l.3 .2M113 62.1h.5M113.2 61.6v1.1l.3 .2M149.9 67.3h.1M149.9 64.8v2.5M280.7 61.6h.1M281.1 60.8h.5M281.3 60.4v1l.3 .2M283.2 61h2.5M290.8 61h2.6M308.6 62.2v2.6M342.9 64.8h.1"/>
<path d="M350.5 64.8h.1M36.8 80h5.1M36.8 82.6h5.1M36.8 85.1h5.1M36.8 87.6h5.1M36.8 90.2h5.1M36.8 92.7h5.1M36.8 95.3h5.1M36.8 97.8h5.1M95.2 82.6h5.1M95.2 85.1h5.1M95.2 87.6h5.1"/>
<path d="M95.2 90.2h5.1M95.2 92.7h5.1M95.2 95.3h5.1M95.2 97.8h5.1M107.9 92.7h1.3M36.8 110.5h5.1M36.8 108h5.1M36.8 100.3h5.1M36.8 102.9h5.1M36.8 113h5.1M36.8 115.6h5.1M36.8 118.1h5.1"/>
<path d="M95.2 110.5h5.1M95.2 108h5.1M95.2 100.3h5.1M95.2 102.9h5.1M95.2 113h5.1M95.2 115.6h5.1M95.2 118.1h5.1M95.2 105.4h5.1M102.9 110.5h1.2M102.9 108h1.2M107.9 118.1h1.3M109.2 110.5h1.3"/>
<path d="M109.2 108h1.3M114.3 110.5h1.3M114.3 108h1.3M120.6 110.5h1.3M120.6 108h1.3M219.7 101.6h.1M222.2 104.1h.1M224.8 104.1h2M233 104.1h1.9M234.9 106.7v3.2M234.9 111.1v3.2M242.6 106.7v3.2"/>
<path d="M242.6 111.1v3.2M260.3 108v3.1M260.3 112.4v3.2M262.9 104.1h2.5a1.27 1.27 0 0 1 1.3-1.2 1.27 1.27 0 0 1 1.3 1.2 1.27 1.27 0 0 1 1.2-1.2 1.27 1.27 0 0 1 1.3 1.2 1.27 1.27 0 0 1 1.3-1.2 1.27 1.27 0 0 1 1.2 1.2 1.27 1.27 0 0 1 1.3-1.2 1.27 1.27 0 0 1 1.3 1.2h2.5M265.4 101.6h10.2M265.4 102.1h10.2M36.8 120.7h5.1M36.8 123.2h5.1M36.8 125.7h5.1M36.8 128.3h5.1M36.8 130.8h5.1M36.8 133.4h5.1"/>
<path d="M36.8 135.9h5.1M36.8 138.4h5.1M95.2 120.7h5.1M95.2 125.7h5.1M95.2 128.3h5.1M95.2 130.8h5.1M95.2 133.4h5.1M95.2 135.9h5.1M95.2 138.4h5.1M36.8 141h5.1M36.8 143.5h5.1M36.8 146.1h5.1"/>
<path d="M36.8 151.1h5.1M36.8 153.7h5.1M36.8 156.2h5.1M36.8 158.8h5.1M95.2 141h5.1M95.2 143.5h5.1M95.2 146.1h5.1M95.2 151.1h5.1M95.2 153.7h5.1M95.2 156.2h5.1M95.2 158.8h5.1M95.2 148.6h5.1"/>
<path d="M142.2 148.6h2.6M149.9 156.2h.1M149.9 141h.1M149.9 141v2.5M149.9 153.7v2.5M154.9 148.6h2.6M36.8 161.3h5.1M36.8 163.8h5.1M36.8 166.4h5.1M36.8 168.9h5.1M36.8 171.5h5.1M36.8 174h5.1"/>
<path d="M36.8 176.5h5.1M36.8 179.1h5.1M95.2 161.3h5.1M95.2 163.8h5.1M95.2 168.9h5.1M95.2 171.5h5.1M95.2 174h5.1M95.2 176.5h5.1M95.2 179.1h5.1M121.9 179.1h.1M121.9 163.8v1.3M121.9 170.2v2.5"/>
<path d="M121.9 177.8v1.3M24.1 196.9v3.1M31.7 196.9v3.1M36.8 181.6h5.1M36.8 184.2h5.1M36.8 186.7h5.1M36.8 189.2h5.1M36.8 194.3h5.1M36.8 196.9h5.1M95.2 181.6h5.1M95.2 184.2h5.1M95.2 186.7h5.1"/>
<path d="M95.2 189.2h5.1M95.2 194.3h5.1M95.2 196.9h5.1M95.2 191.8h5.1M95.2 199.4h5.1M24.1 204.5h.1M24.1 201.3v3.2M31.7 204.5h.1M31.7 201.3v3.2M67.3 212.1v5.1M69.8 212.1v5.1M95.2 201.9h5.1"/>
<path d="M95.2 204.5h5.1M95.2 207h5.1M315 214.6h.1M315 214.6v3.2M315 219.1v3.1M322.6 214.6v3.2M322.6 219.1v3.1M328.9 214.6v3.2M328.9 219.1v3.1M336.5 214.6v3.2M336.5 219.1v3.1M344.2 214.6v3.2"/>
<path d="M344.2 219.1v3.1M350.5 214.6v3.2M350.5 219.1v3.1M356.9 214.6v3.2M356.9 219.1v3.1M302.3 236.2v3.2M309.9 236.2v3.2M315 222.2h.1M317.5 236.2v3.2M322.6 222.2h.1M325.1 236.2v3.2M328.9 222.2h.1"/>
<path d="M331.5 236.2v3.2M336.5 222.2h.1M337.8 236.2v3.2M344.2 222.2h.1M344.2 236.2v3.2M350.5 222.2h.1M350.5 236.2v3.2M356.9 222.2h.1M356.9 236.2v3.2M378.5 226.1h.1M378.5 223.5v2.6M386.1 226.1h.1"/>
<path d="M386.1 223.5v2.6M393.7 226.1h.1M393.7 223.5v2.6M63.3 248.9h7.1v2.6h-7.1l-1.1-1.3zM63.3 254h7.6v2.5h-7.6l-1.1-1.2zM63.3 259.1h5.4v2.5h-5.4l-1.1-1.3zM63.3 256.5h7.2v2.6h-7.2l-1.1-1.3zM63.9 249.2h5.5M113 250.2h2.6M113 252.7h2.6M113 255.3h2.6M113 257.8h2.6"/>
<path d="M151.1 256.5v1.3h1.3l-1.3 1.3-1.2-1.3h1.2M151.1 256.5h.1M151.1 248.9v3.2M151.1 253.4v3.1M157.5 243.8v-1.2l-1.3 1.2 1.3 1.3v-1.3h1.2M158.7 243.8h.1M158.7 243.8h2.6M161.3 241.3h10.1v10.2h-10.1zM165.1 246.4h-1.3v2.5h-5.1M165.1 244.6v3.6M165.6 244.6h1.5v3.6h-1.5zM167.6 244.6v3.6"/>
<path d="M171.4 248.9h2.6M174 243.8h-5.1v2.6h-1.3M174 248.9h1.3v-1.3l1.2 1.3-1.2 1.3v-1.3M174 248.9h.1M182.9 256.5v1.3h1.2l-1.2 1.3-1.3-1.3h1.3M182.9 256.5h.1M182.9 248.9v3.2M182.9 253.4v3.1M302.3 243.8h.1M302.3 240.7v3.1M309.9 243.8h.1M309.9 240.7v3.1"/>
<path d="M317.5 243.8h.1M317.5 240.7v3.1M325.1 243.8h.1M325.1 240.7v3.1M331.5 243.8h.1M331.5 240.7v3.1M337.8 243.8h.1M337.8 240.7v3.1M344.2 243.8h.1M344.2 240.7v3.1M350.5 243.8h.1M350.5 240.7v3.1"/>
<path d="M356.9 243.8h.1M356.9 240.7v3.1M378.5 242.6h.1M378.5 240v2.6M386.1 242.6h.1M386.1 240v2.6M393.7 242.6h.1M393.7 240v2.6M113 260.3h2.6M113 262.9h2.6M115.6 262.9h.1M124.5 260.3h.1"/>
</g>
<g fill="none" stroke="#006464" stroke-width=".18">
<path d="M33.7 35.5h.3M33.7 35.1h.4M55 27l-.5 1.3M282.8 30.1h.8M282.8 37.9h.8M282.8 38.4a.39 .39 0 0 1 .5-.2 .39 .39 0 0 1 .2 .4 .39 .39 0 0 1-.4 .2 .39 .39 0 0 1-.3-.4zM283 29.8l.3 .3M283 31.7h.6M283 37.6l.3 .3M283.3 31.6v.5l-.6-.2M283.5 31.3h.1M283.6 28.9v.2h-.2a.34 .34 0 0 0-.4-.2 .34 .34 0 0 0-.2 .5l.4 .1 .4-.2v.2"/>
<path d="M283.6 30.8l-.8-.4v.6M283.6 36.7v.2h-.2a.34 .34 0 0 0-.4-.2 .34 .34 0 0 0-.2 .5l.4 .1 .4-.2v.2M283.6 29.8l-.3 .2M283.6 39v.5M283.6 39.3h-.8l.2 .2M283.6 37.6l-.3 .3M303.7 28.5h.7M322.7 31.3h-.4v.4h.4v.3h-.4M322.7 33.9h-.4v.3h.4v.4h-.4M323.1 32.1h.1M323.1 32v.1M323.1 34.6v.1"/>
<path d="M323.4 32.1h.5M323.4 31.5l.2-.2v.8M323.4 34.1l.2-.2v.8M323.4 34.7h.5M324.2 31.3v.8M324.2 33.9v.8M324.3 31.8l.2 .3M324.3 34.3l.2 .4M324.5 31.6l-.3 .3M324.5 34.1l-.3 .3M324.8 32.1h.2v-.1a.34 .34 0 0 1-.2-.5 .34 .34 0 0 1 .5-.1l.1 .3-.2 .4h.2M324.8 34.7h.2v-.2a.34 .34 0 0 1-.2-.5 .34 .34 0 0 1 .5-.1l.1 .4-.2 .4h.2"/>
<path d="M335.4 39.5h1M355.9 20.8l-.3 .9h.8M356.2 21.3v.9M356.9 21.6l.6-.1 .1-.2-.1-.3-.6-.1v1.3M32.7 59.3h-.1a.39 .39 0 0 0-.3 .4 .39 .39 0 0 0 .4 .3M32.7 59.3h.1M32.7 59.3v.7M32.7 60h.1M152.7 47.3l-.4 1.3M170.8 55.7l.5 .7M171.3 55.1l-.7 .7M304.6 50.9l.2 .2-.2 .4"/>
<path d="M305.8 50.9h-.3a.86 .86 0 0 0 0 1.2l.4-.1 .1-.4-.3-.2h-.3l-.2 .2M335.4 42h1M33.1 60.1h.2v-.2a.34 .34 0 0 1-.2-.5 .34 .34 0 0 1 .5-.1l.1 .4-.2 .4h.2M93.9 74.8l.5 .7M93.9 60.3h.6M94.2 71.8a.9 .9 0 0 1 0 1.1M94.4 74.2l-.7 .8M302.1 63.7l.2-.1a.68 .68 0 0 1 .4 .6 .68 .68 0 0 1-.4 .6l-.2-.1M303.9 64.1l-.2 .3h-.3l-.2-.3v-.3l.2-.2h.3l.2 .2a.84 .84 0 0 1-.3 1h-.3M304.5 63.7l.2-.1a.68 .68 0 0 1 .4 .6 .68 .68 0 0 1-.4 .6l-.3-.4zM46.5 93.3h.7M93.9 98.4h.6"/>
<path d="M105.1 92.3h-.1a.39 .39 0 0 0-.3 .4 .39 .39 0 0 0 .4 .3M105.1 92.3h.1M105.1 92.3v.7M105.1 93h.1M105.5 93.1h.2v-.2a.34 .34 0 0 1-.2-.4 .34 .34 0 0 1 .5-.2l.1 .4-.2 .4h.2M222.6 96.8l-.4 1.3M93.9 108.5h.6M104.8 117.7h.1a.39 .39 0 0 1 .3 .4 .39 .39 0 0 1-.4 .3l-.1-.2zM105.5 118.5h.2v-.2a.34 .34 0 0 1-.2-.4 .34 .34 0 0 1 .5-.2l.1 .4-.2 .4h.2M106.1 110.1h.1a.39 .39 0 0 1 .3 .4 .39 .39 0 0 1-.4 .3l-.1-.3zM106.1 107.6l.1-.1a.39 .39 0 0 1 .3 .4 .39 .39 0 0 1-.4 .4l-.1-.3zM106.8 110.9h.1v-.2a.34 .34 0 0 1-.1-.5 .34 .34 0 0 1 .5-.1l.1 .4-.2 .4h.2"/>
<path d="M106.8 108.3h.1v-.1a.34 .34 0 0 1-.1-.5 .34 .34 0 0 1 .5-.1l.1 .3-.2 .4h.2M117.5 110.1h.1a.39 .39 0 0 1 .3 .4 .39 .39 0 0 1-.4 .3l-.1-.3zM117.5 107.6l.1-.1a.39 .39 0 0 1 .3 .4 .39 .39 0 0 1-.4 .4l-.1-.3zM118.2 110.9h.2v-.2a.34 .34 0 0 1-.2-.5 .34 .34 0 0 1 .5-.1l.1 .4-.2 .4h.2M118.2 108.3h.2v-.1a.34 .34 0 0 1-.2-.5 .34 .34 0 0 1 .5-.1l.1 .3-.2 .4h.2M231 104.7h.7M231.4 103.4v1.3M240 110.1h.4M247.6 110.1h.4M266.2 111.7h.2M266.2 111.3h.3M46.3 136.5h.8"/>
<path d="M58.4 122.5h.8l-.4 .5M58.5 131.4h.7M58.7 130.3l.1-.2v1.3M59 125l.2 .3-.1 .3-.7 .7h.8M59.1 123l.1 .2-.1 .5M59.1 127.7l.1 .4-.1 .6M152.7 136.2l-.4 1.3M93.7 154.2h.7M170.8 144.6l.5 .7M171.3 144l-.7 .7M46.4 179.6h.7M121.5 167.8h.8"/>
<path d="M121.5 175.5h.8M121.7 167.5l.4 .3M121.7 175.2l.4 .3M122.3 166.6v.2h-.2a.34 .34 0 0 0-.4-.2 .34 .34 0 0 0-.2 .5l.4 .1 .4-.2v.2M122.3 168.2v.4M122.3 174.3v.1h-.2a.34 .34 0 0 0-.4-.1 .34 .34 0 0 0-.2 .4l.4 .2 .4-.2v.2M122.3 175.8v.5l-.6-.5-.2 .2 .1 .3M122.3 168.4h-.8l.2 .2M122.3 167.5l-.3 .3M122.3 175.2l-.3 .2M93.7 197.4h.7M29.6 200.6h.2"/>
<path d="M29.6 200.2h.3M37.2 200.6h.2M37.2 200.2h.4M86.9 217h.4l.2 .2-.1 .5h-.5M87.4 216.5l-.4 .1M317.7 208.9l-.4 1.2M172.6 239.6l.5 .2 .1 .3-.2 .3-.5-.1M173.2 239.1h-.4l-.2 .1M173.8 239.1v1.3M113.7 243.6h.3M114 243.1v1.3M114 244.4h-.3"/>
<path d="M114.6 244l.6-.1-.1-.3h-.3l-.2 .2v.6h.5M115.7 243.6v.8M116.1 243.6l-.4 .2M148 252.3h.4M187.9 252.3h.4M125.1 262.2l-.5 1.3"/>
</g>
<path d="M104.1 106.9h5.1v2.1h-5.1zM104.1 109.5h5.1v2h-5.1zM115.6 109.5h5v2h-5zM115.6 106.9h5v2.1h-5zM259.1 111.1h2.5M259.1 112.4h2.5M149.9 252.1h2.5M149.9 253.4h2.5M181.6 252.1h2.5M181.6 253.4h2.5" fill="none" stroke="#840000" stroke-width=".25"/>
<g fill="none" stroke="#009600" stroke-width=".18">
<path d="M31.7 39.4h5.1M52.1 31.8h33M100.3 39.4h14M271.8 26.7h55.9M283.2 34.3h2.5M327.7 39.4v2.5M370.8 33h15.3M370.8 30.5h15.3M370.8 35.6h15.3M370.8 38.1h15.3M398.8 30.5h2.5v76.2M398.8 33h2.5"/>
<path d="M398.8 35.6h2.5M398.8 38.1h2.5M19 59.7h10.2M19 41.9h17.8M21.6 47h3.8M29.2 57.2h7.6M33 47h3.8M100.3 59.7h14M100.3 57.2h10.2M100.3 41.9h14M100.3 47h10.2M100.3 54.6h10.2"/>
<path d="M100.3 52.1h10.2M100.3 49.5h10.2M100.3 44.5h14M121.9 59.7h20.3M157.5 59.7h34.3M293.4 55.9h10.1v1.3M303.5 59.7v1.3h-10.1M327.7 45.7h-6.4v14h-7.6M327.7 40.6h-10.2v16.6h-3.8M327.7 44.5v2.5M370.8 58.4h15.3M370.8 53.3h15.3"/>
<path d="M370.8 45.7h15.3M370.8 48.3h15.3M370.8 43.2h15.3M370.8 55.9h15.3M370.8 40.6h15.3M370.8 50.8h15.3M398.8 58.4h2.5M398.8 53.3h2.5M398.8 45.7h2.5M398.8 48.3h2.5M398.8 43.2h2.5M398.8 55.9h2.5"/>
<path d="M398.8 40.6h2.5M398.8 50.8h2.5M19 74.9h17.8M19 67.3h17.8M19 77.5h17.8M19 64.8h17.8M370.8 76.2h15.3M370.8 73.7h15.3M370.8 78.7h15.3M370.8 61h15.3M370.8 63.5h15.3M370.8 66h15.3"/>
<path d="M370.8 71.1h15.3M398.8 76.2h2.5M398.8 73.7h2.5M398.8 78.7h2.5M398.8 61h2.5M398.8 63.5h2.5M398.8 68.6h2.5M398.8 66h2.5M398.8 71.1h2.5M19 80h17.8M21.6 92.7h15.2M21.6 95.3h15.2"/>
<path d="M21.6 97.8h15.2M100.3 97.8h22.9M100.3 87.6h22.9M100.3 85.1h22.9M100.3 82.6h22.9M100.3 90.2h22.9M123.2 92.7h-14v2.6M370.8 81.3h15.3M370.8 86.4h15.3M370.8 94h15.3M370.8 91.4h15.3M370.8 88.9h15.3"/>
<path d="M370.8 96.5h15.3M370.8 99.1h15.3M370.8 83.8h15.3M398.8 81.3h2.5M398.8 86.4h2.5M398.8 94h2.5M398.8 91.4h2.5M398.8 88.9h2.5M398.8 96.5h2.5M398.8 99.1h2.5M398.8 83.8h2.5M100.3 100.3h22.9"/>
<path d="M100.3 105.4h22.9M100.3 115.6h22.9M110.5 108h3.8M110.5 110.5h3.8M121.9 108h15.3M121.9 110.5h15.3M123.2 118.1h-14v2.6M219.7 101.6v2.5h5.1M234.9 114.3v2.5M242.6 104.1v2.6M242.6 114.3v2.5M252.7 104.1v2.6"/>
<path d="M252.7 116.8v7.7M260.3 104.1v3.9M260.3 115.6v3.8M262.9 104.1h-28v2.6M278.1 104.1h2.6M280.7 109.2h-12.7v10.2h-15.3M311.1 109.2h10.2M311.1 114.3h2.6v5.1M331.5 104.1v5.1h-2.6M339.1 104.1v3.9M339.1 115.6v3.8M349.2 104.1v3.9"/>
<path d="M349.2 115.6v3.8M351.8 101.6v2.5h-40.7M370.8 104.1h15.3M370.8 101.6h15.3M398.8 104.1h2.5M398.8 101.6h2.5M19 130.8h17.8M19 125.7h17.8M19 133.4h17.8M19 128.3h17.8M19 123.2h17.8M22.9 135.9h13.9"/>
<path d="M22.9 138.4h13.9M100.3 130.8h22.9M100.3 125.7h22.9M100.3 133.4h22.9M100.3 128.3h22.9M100.3 135.9h22.9M100.3 138.4h22.9M252.7 132.1v2.5M372.1 121.9h14M372.1 127h14M372.1 129.5h14M372.1 124.5h14"/>
<path d="M372.1 139.7h14M372.1 137.2h14M372.1 132.1h14M372.1 134.6h14M398.8 121.9h2.5v76.2M398.8 127h2.5M398.8 129.5h2.5M398.8 124.5h2.5M398.8 139.7h2.5M398.8 137.2h2.5M398.8 132.1h2.5M398.8 134.6h2.5"/>
<path d="M22.9 141h13.9M22.9 146.1h13.9M22.9 143.5h13.9M100.3 148.6h41.9M157.5 148.6h30.5M372.1 144.8h14M372.1 149.9h14M372.1 147.3h14M372.1 152.4h14M372.1 157.5h14M372.1 154.9h14M372.1 142.2h14"/>
<path d="M398.8 144.8h2.5M398.8 149.9h2.5M398.8 147.3h2.5M398.8 152.4h2.5M398.8 157.5h2.5M398.8 154.9h2.5M398.8 142.2h2.5M22.9 179.1h13.9M22.9 176.5h13.9M22.9 174h13.9M22.9 171.5h13.9M22.9 168.9h13.9"/>
<path d="M107.9 163.8h14M121.9 171.5h20.3M372.1 172.7h14M372.1 170.2h14M372.1 177.8h14M372.1 175.3h14M372.1 165.1h14M372.1 167.6h14M372.1 160h14M372.1 162.6h14M398.8 172.7h2.5M398.8 170.2h2.5"/>
<path d="M398.8 177.8h2.5M398.8 175.3h2.5M398.8 165.1h2.5M398.8 167.6h2.5M398.8 160h2.5M398.8 162.6h2.5M22.9 184.2h13.9M22.9 186.7h13.9M22.9 189.2h13.9M22.9 181.6h13.9M31.7 196.9h5.1M36.8 194.3h-12.7v2.6"/>
<path d="M372.1 180.3h14M372.1 185.4h14M372.1 182.9h14M372.1 188h14M372.1 190.5h14M372.1 195.6h14M372.1 193h14M398.8 180.3h2.5M398.8 185.4h2.5M398.8 182.9h2.5M398.8 188h2.5M398.8 190.5h2.5"/>
<path d="M398.8 195.6h2.5M398.8 193h2.5M69.8 217.2h-2.5v5M315 214.6h41.9M49.5 238.8v3.8M302.3 234.9v1.3h54.6M115.6 255.3h10.1M115.6 252.7h10.1M115.6 250.2h10.1M115.6 257.8h10.1M151.1 248.9h7.6M174 243.8h8.9v5.1"/>
<path d="M47 273v3.9M49.5 273v1.3h-2.5M115.6 260.3h8.9"/>
</g>
<g fill="none" stroke="#000084" stroke-width=".18">
<path d="M36.2 51.5l1.2 1.2M37.4 51.5l-1.2 1.2M36.2 71.8l1.2 1.2M36.2 69.2l1.2 1.3M37.4 71.8l-1.2 1.2M37.4 69.2l-1.2 1.3M99.7 76.9l1.2 1.2M99.7 64.2l1.2 1.2M100.9 76.9l-1.2 1.2M100.9 64.2l-1.2 1.2M385.5 68l1.2 1.2M386.7 68l-1.2 1.2"/>
<path d="M36.2 89.6l1.2 1.2M36.2 87l1.2 1.2M36.2 84.5l1.2 1.2M36.2 99.7l1.2 1.2M36.2 81.9l1.2 1.3M37.4 89.6l-1.2 1.2M37.4 87l-1.2 1.2M37.4 84.5l-1.2 1.2M37.4 99.7l-1.2 1.2M37.4 81.9l-1.2 1.3M36.2 102.3l1.2 1.2M36.2 117.5l1.2 1.2"/>
<path d="M36.2 115l1.2 1.2M36.2 112.4l1.2 1.2M36.2 108.6l1.2 1.2M36.2 107.3l1.2 1.3M37.4 102.3l-1.2 1.2M37.4 117.5l-1.2 1.2M37.4 115l-1.2 1.2M37.4 112.4l-1.2 1.2M37.4 108.6l-1.2 1.2M37.4 107.3l-1.2 1.3M99.7 112.4l1.2 1.2M99.7 102.3l1.2 1.2"/>
<path d="M100.9 112.4l-1.2 1.2M100.9 102.3l-1.2 1.2M280.1 113.7l1.2 1.2M281.3 113.7l-1.2 1.2M36.2 120l1.2 1.3M37.4 120l-1.2 1.3M36.2 158.1l1.2 1.3M36.2 155.6l1.2 1.2M36.2 150.5l1.2 1.2M36.2 153.1l1.2 1.2M37.4 158.1l-1.2 1.3M37.4 155.6l-1.2 1.2"/>
<path d="M37.4 150.5l-1.2 1.2M37.4 153.1l-1.2 1.2M99.7 142.9l1.2 1.2M99.7 140.4l1.2 1.2M99.7 145.4l1.2 1.3M99.7 150.5l1.2 1.2M99.7 153.1l1.2 1.2M99.7 155.6l1.2 1.2M99.7 158.1l1.2 1.3M100.9 142.9l-1.2 1.2M100.9 140.4l-1.2 1.2M100.9 145.4l-1.2 1.3"/>
<path d="M100.9 150.5l-1.2 1.2M100.9 153.1l-1.2 1.2M100.9 155.6l-1.2 1.2M100.9 158.1l-1.2 1.3M36.2 160.7l1.2 1.2M36.2 165.8l1.2 1.2M36.2 163.2l1.2 1.2M37.4 160.7l-1.2 1.2M37.4 165.8l-1.2 1.2M37.4 163.2l-1.2 1.2M99.7 160.7l1.2 1.2M99.7 163.2l1.2 1.2"/>
<path d="M99.7 168.3l1.2 1.2M99.7 170.8l1.2 1.3M99.7 173.4l1.2 1.2M99.7 175.9l1.2 1.2M99.7 178.5l1.2 1.2M100.9 160.7l-1.2 1.2M100.9 163.2l-1.2 1.2M100.9 168.3l-1.2 1.2M100.9 170.8l-1.2 1.3M100.9 173.4l-1.2 1.2M100.9 175.9l-1.2 1.2M100.9 178.5l-1.2 1.2"/>
<path d="M99.7 198.8l1.2 1.2M99.7 196.2l1.2 1.3M99.7 193.7l1.2 1.2M99.7 181l1.2 1.2M99.7 191.2l1.2 1.2M99.7 188.6l1.2 1.2M99.7 186.1l1.2 1.2M99.7 183.5l1.2 1.3M100.9 198.8l-1.2 1.2M100.9 196.2l-1.2 1.3M100.9 193.7l-1.2 1.2M100.9 181l-1.2 1.2"/>
<path d="M100.9 191.2l-1.2 1.2M100.9 188.6l-1.2 1.2M100.9 186.1l-1.2 1.2M100.9 183.5l-1.2 1.3M99.7 201.3l1.2 1.2M99.7 206.4l1.2 1.2M99.7 203.9l1.2 1.2M100.9 201.3l-1.2 1.2M100.9 206.4l-1.2 1.2M100.9 203.9l-1.2 1.2M61.6 262.3l1.2 1.2M62.8 262.3l-1.2 1.2"/>
</g>
<g fill="none" stroke="#0000c2" stroke-width=".18">
<path d="M397.2 16.1l-.6-.1-.4 .4 .1 .3 .9 .3 .1 .2-.1 .4-.2 .1-.8-.1M296.8 124h.8M297 125.4l.2-.1a.68 .68 0 0 1 .4 .7 .68 .68 0 0 1-.4 .6l-.3-.5zM297.6 122.9v.4M299.1 123.6h1M299.1 126.1h1M301.6 124h.7M301.6 123.1l.4-.3v1.2M301.6 125.7l.4-.4v1.3M301.6 126.6h.7M51.2 216.3h1M307.3 210v2.1a.69 .69 0 0 1-1.1 .4"/>
<path d="M307.3 210.2l-.7-.2-.5 .5v.8l.2 .3 .3 .1 .7-.1M379.2 211.9l.2 .1 .8-.1M379.2 210.4l.2-.1 .8 .1M380.2 210.3v2.1a.69 .69 0 0 1-.9 .4M94.8 231.5h.6a.69 .69 0 0 1 .4 1.1l-1.5 1.5h1.6M116.5 232.4v1.7M117.2 232.4a.65 .65 0 0 0-.7 .5M166 232.3v2.2l.3 .4M184.5 233.2l.5 .4v.8l-.5 .5M186 233.2v1.7M186.8 233.2a.65 .65 0 0 0-.8 .4"/>
</g>
<path d="M14 12.7h193v215.9h-193zM260.3 12.7h99.1v63.5h-99.1zM363.2 14h41.9v191.7h-41.9zM284.5 207h76.2v43.2h-76.2zM363.2 208.3h41.9v43.2h-41.9zM14 229.9h60.9v53.3h-60.9zM76.2 229.9h61v40.6h-61zM138.4 229.9h61v35.5h-61z" fill="none" stroke="#0000c2" stroke-width=".18" stroke-dasharray="1.7 .6"/>
<g fill="none" stroke="#a90000" stroke-width=".18">
<path d="M74.5 32.7v.7M77.1 32.7v.7M79.2 32.7v.7M98 51.7h.8M39.6 79.6h.7M98.6 64.4h.8M98.6 61.8h.8M98.6 69h.8M99.3 63.2v.4M40.2 93.6h.8l-.5 1.2M40.2 86.8h.8M98.6 98.6h.8l-.5 1.3"/>
<path d="M98.6 91.9h.8M39.6 110.1h.7M40.2 102.5h.7M40.9 101.3v.4M39.6 130.4h.7M40.2 153.3h.7M40.2 150.7h.7M40.9 152.1v.4M98.6 153.3h.8M98.6 150.7h.8M99.3 152.1v.4M98.6 174.8h.8l-.5 1.3"/>
<path d="M98.6 168.1h.8M39.6 193.9h.7M98 199h.8M98.6 183.7h.8M99.3 182.6v.4M69.4 213.7v.7"/>
</g>
<path d="M104.8 94.9l.1-.1a.39 .39 0 0 1 .3 .4 .39 .39 0 0 1-.4 .4l-.1-.3zM105.5 95.6h.2v-.1a.34 .34 0 0 1-.2-.5 .34 .34 0 0 1 .5-.1l.1 .3-.2 .4h.2M105.1 120.3l-.1-.1a.39 .39 0 0 0-.3 .4 .39 .39 0 0 0 .4 .4M105.1 120.3h.1M105.1 120.3v.6M105.1 120.9v.1M105.5 121h.2v-.1a.34 .34 0 0 1-.2-.5 .34 .34 0 0 1 .5-.1l.1 .3-.2 .4h.2" fill="none" stroke="#989898" stroke-width=".18"/>
<path d="M107.9 95.3h1.3M107.9 120.7h1.3" fill="none" stroke="#a1a1a1" stroke-width=".18"/>
<path d="M101.8 93.8l7.2 2.9M109 93.8l-7.2 2.9M101.8 119.2l7.2 2.9M109 119.2l-7.2 2.9" fill="none" stroke="#e12e31" stroke-width=".46"/>
<path d="M29.3 202.8l-.3 .8M36.9 202.8l-.3 .8" fill="none" stroke="#840084" stroke-width=".18"/>
<g fill="#009600" stroke="#009600" stroke-width=".18">
<circle cx="401.3" cy="180.3" r=".46"/>
<circle cx="401.3" cy="175.3" r=".46"/>
<circle cx="401.3" cy="177.8" r=".46"/>
<circle cx="401.3" cy="182.9" r=".46"/>
<circle cx="401.3" cy="185.4" r=".46"/>
<circle cx="401.3" cy="162.6" r=".46"/>
<circle cx="401.3" cy="165.1" r=".46"/>
<circle cx="401.3" cy="188" r=".46"/>
<circle cx="401.3" cy="190.5" r=".46"/>
<circle cx="401.3" cy="195.6" r=".46"/>
<circle cx="401.3" cy="193" r=".46"/>
<circle cx="315" cy="214.6" r=".46"/>
<circle cx="328.9" cy="214.6" r=".46"/>
<circle cx="322.6" cy="214.6" r=".46"/>
<circle cx="302.3" cy="236.2" r=".46"/>
<circle cx="309.9" cy="236.2" r=".46"/>
<circle cx="325.1" cy="236.2" r=".46"/>
<circle cx="317.5" cy="236.2" r=".46"/>
<circle cx="336.5" cy="214.6" r=".46"/>
<circle cx="344.2" cy="214.6" r=".46"/>
<circle cx="344.2" cy="236.2" r=".46"/>
<circle cx="337.8" cy="236.2" r=".46"/>
<circle cx="350.5" cy="236.2" r=".46"/>
<circle cx="331.5" cy="236.2" r=".46"/>
<circle cx="350.5" cy="214.6" r=".46"/>
<circle cx="401.3" cy="38.1" r=".46"/>
<circle cx="401.3" cy="40.6" r=".46"/>
<circle cx="401.3" cy="50.8" r=".46"/>
<circle cx="401.3" cy="55.9" r=".46"/>
<circle cx="401.3" cy="53.3" r=".46"/>
<circle cx="401.3" cy="33" r=".46"/>
<circle cx="401.3" cy="35.6" r=".46"/>
<circle cx="401.3" cy="48.3" r=".46"/>
<circle cx="401.3" cy="45.7" r=".46"/>
<circle cx="401.3" cy="43.2" r=".46"/>
<circle cx="401.3" cy="137.2" r=".46"/>
<circle cx="401.3" cy="157.5" r=".46"/>
<circle cx="401.3" cy="154.9" r=".46"/>
<circle cx="401.3" cy="147.3" r=".46"/>
<circle cx="401.3" cy="149.9" r=".46"/>
<circle cx="401.3" cy="144.8" r=".46"/>
<circle cx="401.3" cy="139.7" r=".46"/>
<circle cx="401.3" cy="142.2" r=".46"/>
<circle cx="401.3" cy="167.6" r=".46"/>
<circle cx="401.3" cy="152.4" r=".46"/>
<circle cx="401.3" cy="160" r=".46"/>
<circle cx="401.3" cy="170.2" r=".46"/>
<circle cx="401.3" cy="172.7" r=".46"/>
<circle cx="401.3" cy="78.7" r=".46"/>
<circle cx="401.3" cy="71.1" r=".46"/>
<circle cx="401.3" cy="68.6" r=".46"/>
<circle cx="401.3" cy="73.7" r=".46"/>
<circle cx="401.3" cy="76.2" r=".46"/>
<circle cx="401.3" cy="63.5" r=".46"/>
<circle cx="401.3" cy="61" r=".46"/>
<circle cx="401.3" cy="66" r=".46"/>
<circle cx="401.3" cy="58.4" r=".46"/>
<circle cx="401.3" cy="104.1" r=".46"/>
<circle cx="401.3" cy="96.5" r=".46"/>
<circle cx="401.3" cy="101.6" r=".46"/>
<circle cx="401.3" cy="86.4" r=".46"/>
<circle cx="401.3" cy="91.4" r=".46"/>
<circle cx="401.3" cy="83.8" r=".46"/>
<circle cx="401.3" cy="134.6" r=".46"/>
<circle cx="401.3" cy="132.1" r=".46"/>
<circle cx="401.3" cy="129.5" r=".46"/>
<circle cx="401.3" cy="124.5" r=".46"/>
<circle cx="401.3" cy="127" r=".46"/>
<circle cx="401.3" cy="81.3" r=".46"/>
<circle cx="327.7" cy="40.6" r=".46"/>
<circle cx="327.7" cy="45.7" r=".46"/>
<circle cx="401.3" cy="94" r=".46"/>
<circle cx="401.3" cy="99.1" r=".46"/>
<circle cx="401.3" cy="88.9" r=".46"/>
<circle cx="252.7" cy="119.4" r=".46"/>
<circle cx="260.3" cy="119.4" r=".46"/>
<circle cx="260.3" cy="104.1" r=".46"/>
<circle cx="252.7" cy="104.1" r=".46"/>
<circle cx="242.6" cy="104.1" r=".46"/>
<circle cx="234.9" cy="104.1" r=".46"/>
<circle cx="222.2" cy="104.1" r=".46"/>
<circle cx="307.3" cy="26.7" r=".46"/>
<circle cx="283.2" cy="26.7" r=".46"/>
<circle cx="283.2" cy="34.3" r=".46"/>
<circle cx="339.1" cy="104.1" r=".46"/>
<circle cx="331.5" cy="104.1" r=".46"/>
<circle cx="349.2" cy="104.1" r=".46"/>
<circle cx="36.8" cy="39.4" r=".46"/>
<circle cx="54.6" cy="31.8" r=".46"/>
<circle cx="52.1" cy="31.8" r=".46"/>
<circle cx="67.3" cy="31.8" r=".46"/>
<circle cx="69.8" cy="31.8" r=".46"/>
<circle cx="57.1" cy="31.8" r=".46"/>
<circle cx="64.8" cy="31.8" r=".46"/>
<circle cx="62.2" cy="31.8" r=".46"/>
<circle cx="59.7" cy="31.8" r=".46"/>
<circle cx="80" cy="31.8" r=".46"/>
<circle cx="77.5" cy="31.8" r=".46"/>
<circle cx="82.5" cy="31.8" r=".46"/>
<circle cx="74.9" cy="31.8" r=".46"/>
<circle cx="72.4" cy="31.8" r=".46"/>
<circle cx="109.2" cy="92.7" r=".46"/>
<circle cx="67.3" cy="217.2" r=".46"/>
<circle cx="47" cy="274.3" r=".46"/>
<circle cx="121.9" cy="171.5" r=".46"/>
<circle cx="109.2" cy="118.1" r=".46"/>
</g>
<use href="#words"/>
</svg>
